# 3065HRPICZ register map
File version: 1.0
Registers are 32-bit, access per field, reset 0x0 unless marked. A register's access mark holds for its fields unless they carry their own. Offsets are from the block's base; [hi:lo] are bit positions.

## APT0 — APT_REG peripheral interface
Base 0x14A00000
Same registers: APT1 0x14A01000, APT2 0x14A02000, APT6 0x14A06000, APT7 0x14A07000, APT8 0x14A08000
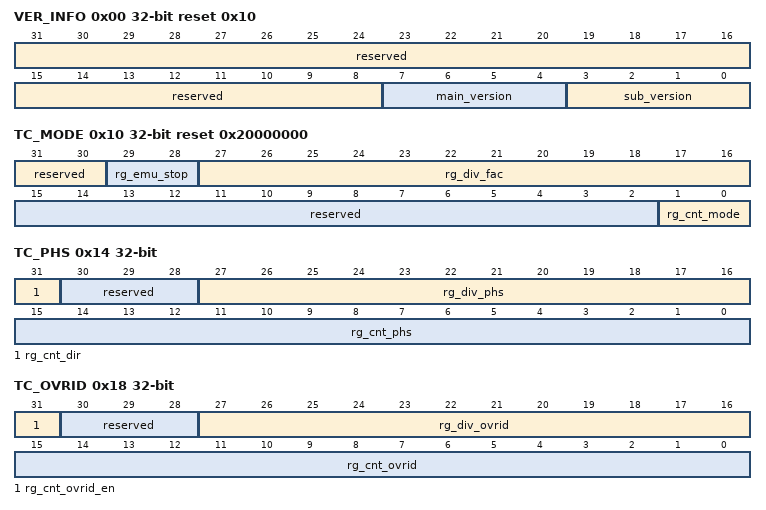
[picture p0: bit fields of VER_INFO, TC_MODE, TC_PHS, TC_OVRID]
0x00 VER_INFO ro reset 0x10 — 版本信息寄存器。
  [31:8] reserved — 保留。
  [7:4] main_version — 主版本号。
  [3:0] sub_version — 子版本号。
0x10 TC_MODE reset 0x20000000 — 计数模式寄存器。
  [31:30] reserved ro — 保留。
  [29:28] rg_emu_stop rw — CPU debug模式，APT停止的方式。注意，如果停止APT，那么在CPU debug模式下，整个APT都会停止工作，包括输出控制功能。 0x：不停止； 10：停止分频计数器（DIVCNT）和时基计数器（TCCNT）； 11：停止APT。
  [27:16] rg_div_fac rw — 分频系数。 分频倍数 =分频系数 +1。
  [15:2] reserved ro — 保留。
  [1:0] rg_cnt_mode rw — 时基计数器（TCCNT）的工作模式。 00：递增计数； 01：递减计数； 10：先增后减计数； 11：冻结。
0x14 TC_PHS — 计数相位控制寄存器。
  [31] rg_cnt_dir rw — 当 APTCNTSYNC 有效时，更新时基计数器（TCCNT）的计数方向，仅在先增后减 计数模式有效。 0：递减； 1：递增。
  [30:28] reserved ro — 保留。
  [27:16] rg_div_phs rw — 当 APTCNTSYNC 有效时，更新分频计数器（DIVCNT）的计数值。
  [15:0] rg_cnt_phs rw — 当 APTCNTSYNC 有效时，更新时基计数器（TCCNT）的计数值。
0x18 TC_OVRID — 计数器初始化寄存器。
  [31] rg_cnt_ovrid_en rw write-1-clears — 时基计数器（TCCNT）和分频计数器（DIVCNT）的初始化使能。 0：无效； 1：初始化时基计数器（TCCNT）和分频计数器（DIVCNT）的计数值。
  [30:28] reserved ro — 保留。
  [27:16] rg_div_ovrid rw — 初始化分频计数(DIVCNT）的计数值。
  [15:0] rg_cnt_ovrid rw — 初始化时基计数（TCCNT）的计数值。
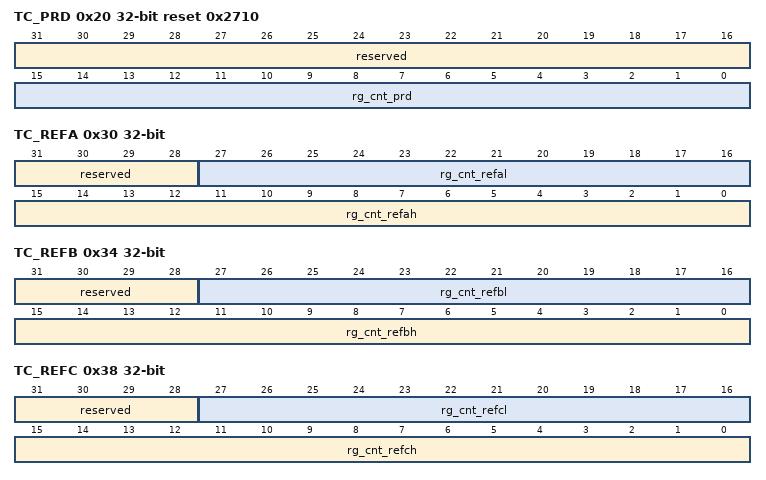
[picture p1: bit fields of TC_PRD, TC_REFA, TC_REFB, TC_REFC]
0x20 TC_PRD reset 0x2710 — 计数周期寄存器。
  [31:16] reserved ro — 保留。
  [15:0] rg_cnt_prd rw — 时基计数器（TCCNT）的计数周期。
0x30 TC_REFA — 计数参考值A寄存器。
  [31:28] reserved ro — 保留。
  [27:16] rg_cnt_refal rw — 分频计数器（DIVCNT）的参考值A，应当小于或等于分频系数。
  [15:0] rg_cnt_refah rw — 时基计数器（TCCNT）的参考值 A，应当小于或等于计数周期。
0x34 TC_REFB — 计数参考值B寄存器。
  [31:28] reserved ro — 保留。
  [27:16] rg_cnt_refbl rw — 分频计数器（DIVCNT）的参考值B，应当小于或等于分频系数。
  [15:0] rg_cnt_refbh rw — 时基计数器（TCCNT）的参考值B，应当小于或等于计数周期。
0x38 TC_REFC — 计数参考值C寄存器。
  [31:28] reserved ro — 保留。
  [27:16] rg_cnt_refcl rw — 分频计数器（DIVCNT）的参考值C，应当小于或等于分频系数。
  [15:0] rg_cnt_refch rw — 时基计数器（TCCNT）的参考值C，应当小于或等于计数周期。
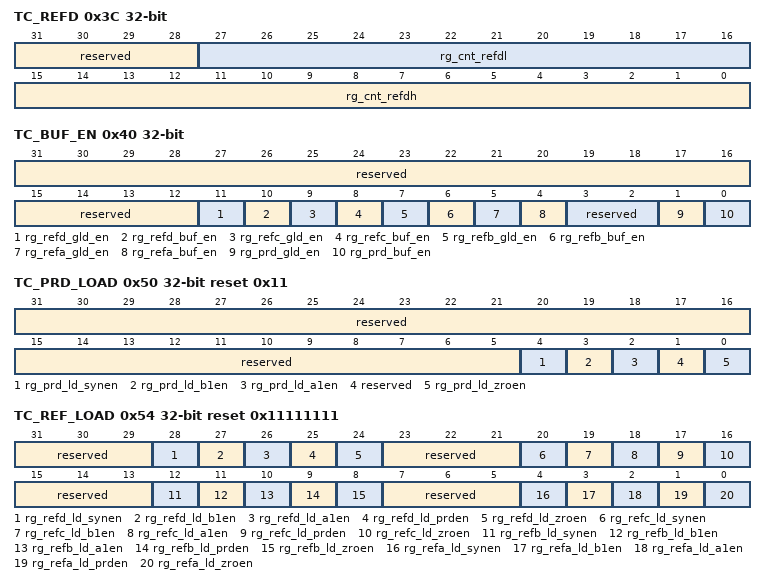
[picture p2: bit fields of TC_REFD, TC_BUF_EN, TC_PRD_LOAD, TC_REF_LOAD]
0x3C TC_REFD — 计数参考值D寄存器。
  [31:28] reserved ro — 保留。
  [27:16] rg_cnt_refdl rw — 分频计数器（DIVCNT）的参考值D，应当小于或等于分频系数。
  [15:0] rg_cnt_refdh rw — 时基计数器（TCCNT）的参考值D，应当小于或等于计数周期。
0x40 TC_BUF_EN — 计数器缓存使能寄存器。
  [31:12] reserved ro — 保留。
  [11] rg_refd_gld_en rw — TC_REFD 寄存器的全局加载使能。 0：不使能； 1：使能。
  [10] rg_refd_buf_en rw — TC_REFD 寄存器的缓存使能。 0：不使能； 1：使能。
  [9] rg_refc_gld_en rw — TC_REFC 寄存器的全局加载使能。 0：不使能； 1：使能。
  [8] rg_refc_buf_en rw — TC_REFC 寄存器的缓存使能。 0：不使能； 1：使能。
  [7] rg_refb_gld_en rw — TC_REFB 寄存器的全局加载使能。 0：不使能； 1：使能。
  [6] rg_refb_buf_en rw — TC_REFB 寄存器的缓存使能。 0：不使能； 1：使能。
  [5] rg_refa_gld_en rw — TC_REFA 寄存器的全局加载使能。 0：不使能； 1：使能。
  [4] rg_refa_buf_en rw — TC_REFA 寄存器的缓存使能。 0：不使能； 1：使能。
  [3:2] reserved ro — 保留。
  [1] rg_prd_gld_en rw — TC_PRD 寄存器的全局加载使能。 0：不使能； 1：使能。
  [0] rg_prd_buf_en rw — TC_PRD 寄存器的缓存使能。 0：不使能； 1：使能。
0x50 TC_PRD_LOAD reset 0x11 — 计数周期寄存器独立加载触发信号选择寄存器。
  [31:5] reserved ro — 保留。
  [4] rg_prd_ld_synen rw — 选择 APTxSYNCI 有效时，是否使能TC_PRD 寄存器的独立加载。 0：不使能； 1：使能。
  [3] rg_prd_ld_b1en rw — 选择 EMEVTB1 有效时，是否使能TC_PRD 寄存器的独立加载。 0：不使能； 1：使能。
  [2] rg_prd_ld_a1en rw — 选择 EMEVTA1 有效时，是否使能TC_PRD 寄存器的独立加载。 0：不使能； 1：使能。
  [1] reserved ro — 保留。
  [0] rg_prd_ld_zroen rw — 选择 CNT_ZERO 有效时，是否使能TC_PRD 寄存器的独立加载。 0：不使能； 1：使能。
0x54 TC_REF_LOAD reset 0x11111111 — 计数参考值寄存器独立加载触发信号选择寄存器。
  [31:29] reserved ro — 保留。
  [28] rg_refd_ld_synen rw — 选择 APTxSYNCI 有效时，是否使能TC_REFD 寄存器的独立加载。 0：不使能； 1：使能。
  [27] rg_refd_ld_b1en rw — 选择 EMEVTB1 有效时，是否使能TC_REFD 寄存器的独立加载。 0：不使能； 1：使能。
  [26] rg_refd_ld_a1en rw — 选择 EMEVTA1 有效时，是否使能TC_REFD 寄存器的独立加载。 0：不使能； 1：使能。
  [25] rg_refd_ld_prden rw — 选择 CNT_PRD 有效时，是否使能TC_REFD 寄存器的独立加载。 0：不使能； 1：使能。
  [24] rg_refd_ld_zroen rw — 选择 CNT_ZERO 有效时，是否使能TC_REFD 寄存器的独立加载。 0：不使能； 1：使能。
  [23:21] reserved ro — 保留。
  [20] rg_refc_ld_synen rw — 选择 APTxSYNCI 有效时，是否使能TC_REFC 寄存器的独立加载。 0：不使能； 1：使能。
  [19] rg_refc_ld_b1en rw — 当选择 EMEVTB1 有效时，是否使能TC_REFC 寄存器的独立加载。 0：不使能； 1：使能。
  [18] rg_refc_ld_a1en rw — 选择 EMEVTA1 有效时，是否使能TC_REFC 寄存器的独立加载。 0：不使能； 1：使能。
  [17] rg_refc_ld_prden rw — 选择 CNT_PRD 有效时，是否使能TC_REFC 寄存器的独立加载。 0：不使能； 1：使能。
  [16] rg_refc_ld_zroen rw — 选择 CNT_ZERO 有效时，是否使能TC_REFC 寄存器的独立加载。 0：不使能； 1：使能。
  [15:13] reserved ro — 保留。
  [12] rg_refb_ld_synen rw — 选择 APTxSYNCI 有效时，是否使能TC_REFB 寄存器的独立加载。 0：不使能； 1：使能。
  [11] rg_refb_ld_b1en rw — 选择 EMEVTB1 有效时，是否使能TC_REFB 寄存器的独立加载。 0：不使能； 1：使能。
  [10] rg_refb_ld_a1en rw — 选择 EMEVTA1 有效时，是否使能TC_REFB 寄存器的独立加载。 0：不使能； 1：使能。
  [9] rg_refb_ld_prden rw — 选择 CNT_PRD 有效时，是否使能TC_REFB 寄存器的独立加载。 0：不使能； 1：使能。
  [8] rg_refb_ld_zroen rw — 选择 CNT_ZERO 有效时，是否使能TC_REFB 寄存器的独立加载。 0：不使能； 1：使能。
  [7:5] reserved ro — 保留。
  [4] rg_refa_ld_synen rw — 选择 APTxSYNCI 有效时，是否使能TC_REFA 寄存器的独立加载。 0：不使能； 1：使能。
  [3] rg_refa_ld_b1en rw — 选择 EMEVTB1 有效时，是否使能TC_REFA 寄存器的独立加载。 0：不使能； 1：使能。
  [2] rg_refa_ld_a1en rw — 选择 EMEVTA1 有效时，是否使能TC_REFA 寄存器的独立加载。 0：不使能； 1：使能。
  [1] rg_refa_ld_prden rw — 选择 CNT_PRD 有效时，是否使能TC_REFA 寄存器的独立加载。 0：不使能； 1：使能。
  [0] rg_refa_ld_zroen rw — 选择 CNT_ZERO 有效时，是否使能TC_REFA 寄存器的独立加载。 0：不使能； 1：使能。
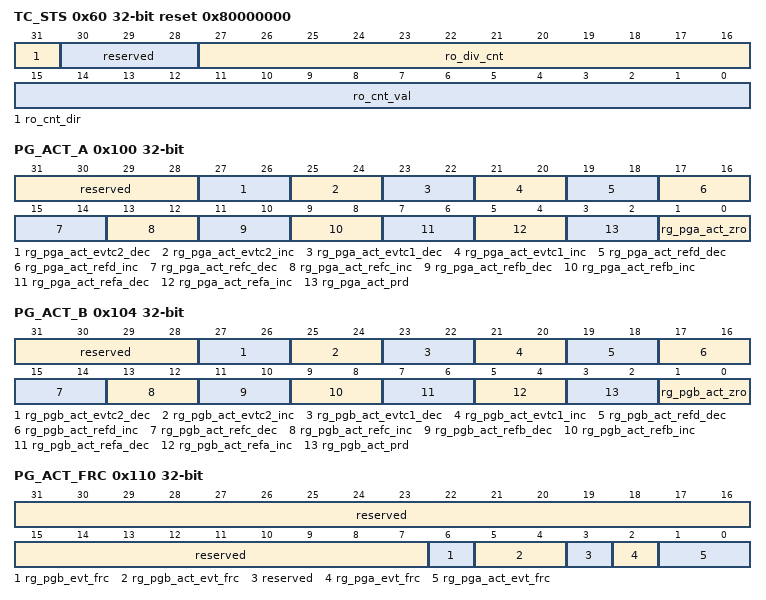
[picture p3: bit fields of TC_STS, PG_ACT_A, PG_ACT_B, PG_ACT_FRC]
0x60 TC_STS ro reset 0x80000000 — 计数状态寄存器。
  [31] ro_cnt_dir — 时基计数器（TCCNT）的当前计数方向。 0：递减计数； 1：递增计数。
  [30:28] reserved — 保留。
  [27:16] ro_div_cnt — 分频计数器（DIVCNT）的当前计数值。
  [15:0] ro_cnt_val — 时基计数器（TCCNT）的当前计数值。
0x100 PG_ACT_A — PG_PWMA 动作配置寄存器。
  [31:28] reserved ro — 保留。
  [27:26] rg_pga_act_evtc2_dec rw — AEVTC2 有效且 TCCNT 计数方向递减时， PG_PWMA 的动作。 00：无影响； 01：置为低电平； 10：置为高电平； 11：翻转电平。
  [25:24] rg_pga_act_evtc2_inc rw — AEVTC2 有效且 TCCNT 计数方向递增时， PG_PWMA 的动作。 00：无影响； 01：置为低电平； 10：置为高电平； 11：翻转电平。
  [23:22] rg_pga_act_evtc1_dec rw — AEVTC1 有效且 TCCNT 计数方向递减时， PG_PWMA 的动作。 00：无影响； 01：置为低电平； 10：置为高电平； 11：翻转电平。
  [21:20] rg_pga_act_evtc1_inc rw — AEVTC1 有效且 TCCNT 计数方向递增时， PG_PWMA 的动作。 00：无影响； 01：置为低电平； 10：置为高电平； 11：翻转电平。
  [19:18] rg_pga_act_refd_dec rw — CNT_REFD 有效且 TCCNT 计数方向递减时， PG_PWMA 的动作。 00：无影响； 01：置为低电平； 10：置为高电平； 11：翻转电平。
  [17:16] rg_pga_act_refd_inc rw — CNT_REFD 有效且 TCCNT 计数方向递增时， PG_PWMA 的动作。 00：无影响； 01：置为低电平； 10：置为高电平； 11：翻转电平。
  [15:14] rg_pga_act_refc_dec rw — CNT_REFC 有效且 TCCNT 计数方向递减时， PG_PWMA 的动作。 00：无影响； 01：置为低电平； 10：置为高电平； 11：翻转电平。
  [13:12] rg_pga_act_refc_inc rw — CNT_REFC 有效且 TCCNT 计数方向递增时， PG_PWMA 的动作。 00：无影响； 01：置为低电平； 10：置为高电平； 11：翻转电平。
  [11:10] rg_pga_act_refb_dec rw — CNT_REFB 有效且 TCCNT 计数方向递减时， PG_PWMA 的动作。 00：无影响； 01：置为低电平； 10：置为高电平； 11：翻转电平。
  [9:8] rg_pga_act_refb_inc rw — CNT_REFB 有效且 TCCNT 计数方向递增时， PG_PWMA 的动作。 00：无影响； 01：置为低电平； 10：置为高电平； 11：翻转电平。
  [7:6] rg_pga_act_refa_dec rw — CNT_REFA 有效且 TCCNT 计数方向递减时， PG_PWMA 的动作。 00：无影响； 01：置为低电平； 10：置为高电平； 11：翻转电平。
  [5:4] rg_pga_act_refa_inc rw — CNT_REFA 有效且 TCCNT 计数方向递增时， PG_PWMA 的动作。 00：无影响； 01：置为低电平； 10：置为高电平； 11：翻转电平。
  [3:2] rg_pga_act_prd rw — CNT_PRD 有效时，PG_PWMA 的动作。 00：无影响； 01：置为低电平； 10：置为高电平； 11：翻转电平。
  [1:0] rg_pga_act_zro rw — CNT_ZERO 有效时,PG_PWMA 的动作。 00：无影响； 01：置为低电平； 10：置为高电平； 11：翻转电平。
0x104 PG_ACT_B — PG_PWMB 动作配置寄存器。
  [31:28] reserved ro — 保留。
  [27:26] rg_pgb_act_evtc2_dec rw — BEVTC2有效且TCCNT计数方向递减时，PG_PWMB的动作。 00：无影响； 01：置为低电平； 10：置为高电平； 11：翻转电平。
  [25:24] rg_pgb_act_evtc2_inc rw — BEVTC2有效且TCCNT计数方向递增时，PG_PWMB的动作。 00：无影响； 01：置为低电平； 10：置为高电平； 11：翻转电平。
  [23:22] rg_pgb_act_evtc1_dec rw — BEVTC1有效且TCCNT计数方向递减时，PG_PWMB的动作。 00：无影响； 01：置为低电平； 10：置为高电平； 11：翻转电平。
  [21:20] rg_pgb_act_evtc1_inc rw — BEVTC1有效且TCCNT计数方向递增时，PG_PWMB的动作。 00：无影响； 01：置为低电平； 10：置为高电平； 11：翻转电平。
  [19:18] rg_pgb_act_refd_dec rw — CNT_REFD 有效且 TCCNT 计数方向递减时， PG_PWMB 的动作。 00：无影响； 01：置为低电平； 10：置为高电平； 11：翻转电平。
  [17:16] rg_pgb_act_refd_inc rw — CNT_REFD 有效且 TCCNT 计数方向递增时， PG_PWMB 的动作。 00：无影响； 01：置为低电平； 10：置为高电平； 11：翻转电平。
  [15:14] rg_pgb_act_refc_dec rw — CNT_REFC 有效且 TCCNT 计数方向递减时， PG_PWMB 的动作。 00：无影响； 01：置为低电平； 10：置为高电平； 11：翻转电平。
  [13:12] rg_pgb_act_refc_inc rw — CNT_REFC 有效且 TCCNT 计数方向递增时， PG_PWMB 的动作。 00：无影响； 01：置为低电平； 10：置为高电平； 11：翻转电平。
  [11:10] rg_pgb_act_refb_dec rw — CNT_REFB 有效且 TCCNT 计数方向递减时， PG_PWMB 的动作。 00：无影响； 01：置为低电平； 10：置为高电平； 11：翻转电平。
  [9:8] rg_pgb_act_refb_inc rw — CNT_REFB 有效且 TCCNT 计数方向递增时， PG_PWMB 的动作。 00：无影响； 01：置为低电平； 10：置为高电平； 11：翻转电平。
  [7:6] rg_pgb_act_refa_dec rw — CNT_REFA 有效且 TCCNT 计数方向递减时， PG_PWMB 的动作。 00：无影响； 01：置为低电平； 10：置为高电平； 11：翻转电平。
  [5:4] rg_pgb_act_refa_inc rw — CNT_REFA 有效且 TCCNT 计数方向递增时， PG_PWMB 的动作。 00：无影响； 01：置为低电平； 10：置为高电平； 11：翻转电平。
  [3:2] rg_pgb_act_prd rw — CNT_PRD 有效时，PG_PWMB 的动作。 00：无影响； 01：置为低电平； 10：置为高电平； 11：翻转电平。
  [1:0] rg_pgb_act_zro rw — CNT_ZERO 有效时,PG_PWMB 的动作。 00：无影响； 01：置为低电平； 10：置为高电平； 11：翻转电平。
0x110 PG_ACT_FRC — 强制动作配置寄存器。
  [31:7] reserved ro — 保留。
  [6] rg_pgb_evt_frc rw write-1-clears — 软件强制 PG_PWMB 动作，每次写 1 产生一次PG_PWMB 动作，然后自动清零。 0：写 0 无效； 1：写 1 有效。
  [5:4] rg_pgb_act_evt_frc rw — 软件强制 PG_PWMB 动作有效时，PG_PWMB 的动作。 00：无影响； 01：置为低电平； 10：置为高电平； 11：翻转电平。
  [3] reserved ro — 保留。
  [2] rg_pga_evt_frc rw write-1-clears — 软件强制 PG_PWMA 动作，每次写 1 产生一次PG_PWMA 动作，然后自动清零。 0：写 0 无效； 1：写 1 有效。
  [1:0] rg_pga_act_evt_frc rw — 软件强制 PG_PWMA 动作有效时，PG_PWMA 的动作。 00：无影响； 01：置为低电平； 10：置为高电平； 11：翻转电平。
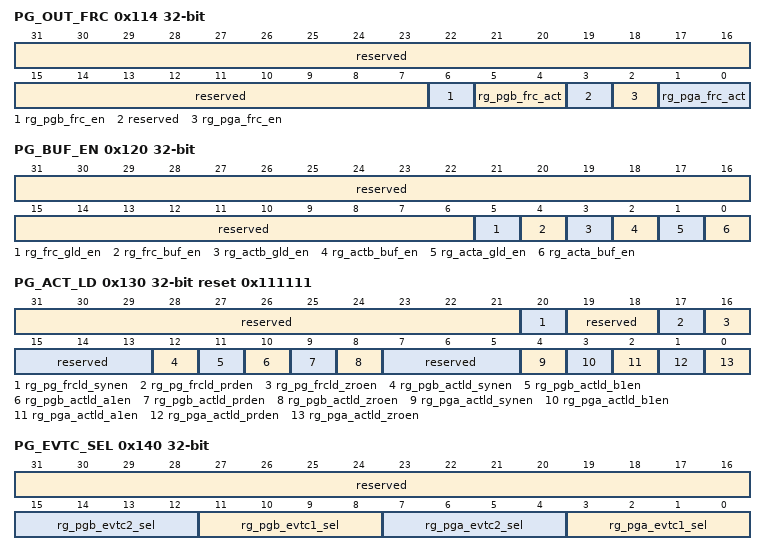
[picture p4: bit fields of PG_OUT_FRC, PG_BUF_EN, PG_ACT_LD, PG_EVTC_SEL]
0x114 PG_OUT_FRC — 强制输出配置寄存器。
  [31:7] reserved ro — 保留。
  [6] rg_pgb_frc_en rw — PG_PWMB 软件强制输出使能。 0：不使能； 1：使能。
  [5:4] rg_pgb_frc_act rw — PG_PWMB 软件强制输出使能时，PG_PWMB 的输出状态。 00：锁定电平； 01：置为低电平； 10：置为高电平； 11：保留。
  [3] reserved ro — 保留。
  [2] rg_pga_frc_en rw — PG_PWMA 软件强制输出使能。 0：不使能； 1：使能。
  [1:0] rg_pga_frc_act rw — PG_PWMA 软件强制输出使能时，PG_PWMA 的输出状态。 00：锁定电平； 01：置为低电平； 10：置为高电平； 11：保留。
0x120 PG_BUF_EN — 波形生成缓存使能寄存器。
  [31:6] reserved ro — 保留。
  [5] rg_frc_gld_en rw — PG_ACT_FRC 寄存器的全局加载使能。 0：不使能； 1：使能。
  [4] rg_frc_buf_en rw — PG_ACT_FRC 寄存器的缓存使能。 0：不使能； 1：使能。
  [3] rg_actb_gld_en rw — PG_ACT_B 寄存器的全局加载使能。 0：不使能； 1：使能。
  [2] rg_actb_buf_en rw — PG_ACT_B 寄存器的缓存使能。 0：不使能； 1：使能。
  [1] rg_acta_gld_en rw — PG_ACT_A 寄存器的全局加载使能。 0：不使能； 1：使能。
  [0] rg_acta_buf_en rw — PG_ACT_A 寄存器的缓存使能。 0：不使能； 1：使能。
0x130 PG_ACT_LD reset 0x111111 — 波形生成动作独立加载触发信号选择寄存器。
  [31:21] reserved ro — 保留。
  [20] rg_pg_frcld_synen rw — 选择 APTxSYNCI 有效时，是否使能PG_ACT_FRC 寄存器的独立加载。 0：不使能； 1：使能。
  [19:18] reserved ro — 保留。
  [17] rg_pg_frcld_prden rw — 选择 CNT_PRD 有效时，是否使能PG_ACT_FRC 寄存器的独立加载。 0：不使能； 1：使能。
  [16] rg_pg_frcld_zroen rw — 选择 CNT_ZERO 有效时，是否使能PG_ACT_FRC 寄存器的独立加载。 0：不使能； 1：使能。
  [15:13] reserved ro — 保留。
  [12] rg_pgb_actld_synen rw — 选择 APTxSYNCI 有效时，是否使能PG_ACT_B 寄存器的独立加载。 0：不使能； 1：使能。
  [11] rg_pgb_actld_b1en rw — 选择 EMEVTB1 有效时，是否使能PG_ACT_B 寄存器的独立加载。 0：不使能； 1：使能。
  [10] rg_pgb_actld_a1en rw — 选择 EMEVTA1 有效时，是否使能PG_ACT_B 寄存器的独立加载。 0：不使能； 1：使能。
  [9] rg_pgb_actld_prden rw — 选择 CNT_PRD 有效时，是否使能PG_ACT_B 寄存器的独立加载。 0：不使能； 1：使能。
  [8] rg_pgb_actld_zroen rw — 选择 CNT_ZERO 有效时，是否使能PG_ACT_B 寄存器的独立加载。 0：不使能； 1：使能。
  [7:5] reserved ro — 保留。
  [4] rg_pga_actld_synen rw — 选择 APTxSYNCI 有效时，是否使能PG_ACT_A 寄存器的独立加载。 0：不使能； 1：使能。
  [3] rg_pga_actld_b1en rw — 选择 EMEVTB1 有效时，是否使能PG_ACT_A 寄存器的独立加载。 0：不使能； 1：使能。
  [2] rg_pga_actld_a1en rw — 选择 EMEVTA1 有效时，是否使能PG_ACT_A 寄存器的独立加载。 0：不使能； 1：使能。
  [1] rg_pga_actld_prden rw — 选择 CNT_PRD 有效时，是否使能PG_ACT_A 寄存器的独立加载。 0：不使能； 1：使能。
  [0] rg_pga_actld_zroen rw — 选择 CNT_ZERO 有效时，是否使能PG_ACT_A 寄存器的独立加载。 0：不使能； 1：使能。
0x140 PG_EVTC_SEL — 波形生成事件 C 触发源选择寄存器。
  [31:16] reserved ro — 保留。
  [15:12] rg_pgb_evtc2_sel rw — BEVTC2 触发源选择。 0x1： EMEVTA1_TEMP； 0x2： EMEVTA2_TEMP； 0x3： EMEVTB1_TEMP； 0x4： EMEVTB2_TEMP； 0x5： EMEVTFILT； 0x6： TRIP1； 0x7： TRIP2； 0x8： TRIP3； 0x9： APTxSYNCI； 其它：禁止产生 BEVTC2。
  [11:8] rg_pgb_evtc1_sel rw — BEVTC1 触发源选择。 0x1： EMEVTA1_TEMP； 0x2： EMEVTA2_TEMP； 0x3： EMEVTB1_TEMP； 0x4： EMEVTB2_TEMP； 0x5： EMEVTFILT； 0x6： TRIP1； 0x7： TRIP2； 0x8： TRIP3； 0x9： APTxSYNCI； 其它：禁止产生 BEVTC1。
  [7:4] rg_pga_evtc2_sel rw — AEVTC2 触发源选择。 0x1： EMEVTA1_TEMP；0x2： EMEVTA2_TEMP； 0x3： EMEVTB1_TEMP； 0x4： EMEVTB2_TEMP； 0x5： EMEVTFILT； 0x6： TRIP1； 0x7： TRIP2； 0x8： TRIP3； 0x9： APTxSYNCI； 其它：禁止产生 AEVTC2。
  [3:0] rg_pga_evtc1_sel rw — AEVTC1 触发源选择。 0x1： EMEVTA1_TEMP； 0x2： EMEVTA2_TEMP； 0x3： EMEVTB1_TEMP； 0x4： EMEVTB2_TEMP； 0x5： EMEVTFILT； 0x6： TRIP1； 0x7： TRIP2； 0x8： TRIP3； 0x9： APTxSYNCI； 其它：禁止产生 AEVTC1。
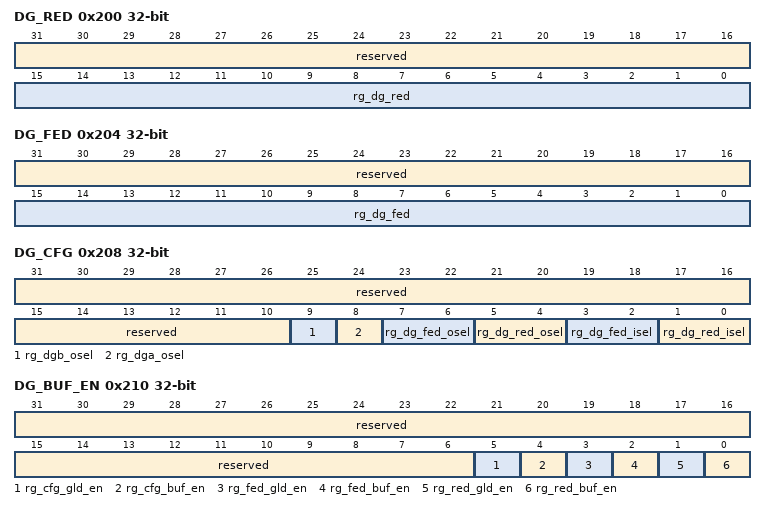
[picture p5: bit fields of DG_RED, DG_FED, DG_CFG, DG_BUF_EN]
0x200 DG_RED — 死区上升沿延时配置寄存器。
  [31:16] reserved ro — 保留。
  [15:0] rg_dg_red rw — 死区上升沿延时配置。
0x204 DG_FED — 死区下降沿延时配置寄存器。
  [31:16] reserved ro — 保留。
  [15:0] rg_dg_fed rw — 死区下降沿延时配置。
0x208 DG_CFG — 死区配置寄存器。
  [31:10] reserved ro — 保留。
  [9] rg_dgb_osel rw — 选择 DG_PWMB 的源。 0：选择 PWM_FED_POL 作为DG_PWMB； 1：选择 PWM_RED_POL 作为DG_PWMB。
  [8] rg_dga_osel rw — 选择 DG_PWMA 的源。 0：选择 PWM_RED_POL 作为DG_PWMA； 1：选择 PWM_FED_POL 作为DG_PWMA。
  [7:6] rg_dg_fed_osel rw — 选择PWM_FED_POL的源。 0x：选择PWM_FED_AFTER作为PWM_FED_POL； 10：选择PWM_FED_AFTER取反后作为PWM_FED_POL； 11：选择PG_PWMB作为PWM_FED_POL。
  [5:4] rg_dg_red_osel rw — 选择PWM_RED_POL的源。 0x：选择PWM_RED_AFTER作为PWM_RED_POL； 10：选择PWM_RED_AFTER取反后作为PWM_RED_POL； 11：选择PG_PWMA作为PWM_RED_POL。
  [3:2] rg_dg_fed_isel rw — 选择PWM_FED_BEFORE的源。 00：选择PG_PWMB作为PWM_FED_BEFORE； 01：选择PG_PWMA作为PWM_FED_BEFORE； 10：选择PWM_RED_BEFORE作为PWM_FED_BEFORE； 11：将PWM_FED_BEFORE固定为低电平。
  [1:0] rg_dg_red_isel rw — 选择PWM_RED_BEFORE的源。 x0：选择PG_PWMA作为PWM_RED_BEFORE； x1：选择PG_PWMB作为PWM_RED_BEFORE。
0x210 DG_BUF_EN — 死区生成缓存使能寄存器。
  [31:6] reserved ro — 保留。
  [5] rg_cfg_gld_en rw — DG_CFG寄存器的全局加载使能。 0：不使能； 1：使能。
  [4] rg_cfg_buf_en rw — DG_CFG寄存器的缓存使能。 0：不使能； 1：使能。
  [3] rg_fed_gld_en rw — DG_CFG寄存器的全局加载使能。 0：不使能； 1：使能。
  [2] rg_fed_buf_en rw — DG_FED寄存器的缓存使能。 0：不使能； 1：使能。
  [1] rg_red_gld_en rw — DG_RED寄存器的全局加载使能。 0：不使能； 1：使能。
  [0] rg_red_buf_en rw — DG_RED寄存器的缓存使能。 0：不使能； 1：使能。
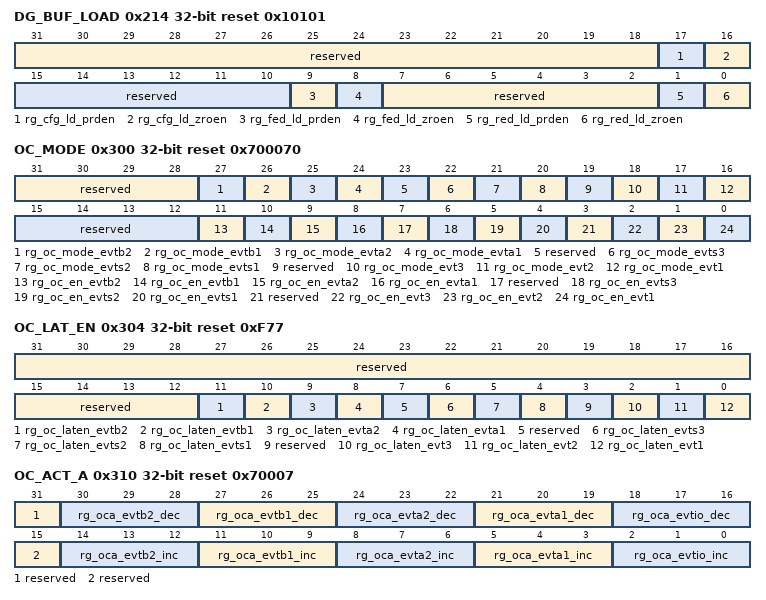
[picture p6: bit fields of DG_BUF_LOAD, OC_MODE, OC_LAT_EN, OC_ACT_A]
0x214 DG_BUF_LOAD reset 0x10101 — 死区生成独立加载触发信号选择寄存器。
  [31:18] reserved ro — 保留。
  [17] rg_cfg_ld_prden rw — 选择CNT_PRD有效时，是否使能DG_CFG寄存器的独立加载。 0：不使能； 1：使能。
  [16] rg_cfg_ld_zroen rw — 选择CNT_ZERO有效时，是否使能DG_CFG寄存器的独立加载。 0：不使能； 1：使能。
  [15:10] reserved ro — 保留。
  [9] rg_fed_ld_prden rw — 选择CNT_PRD有效时，是否使能DG_FED寄存器的独立加载。 0：不使能； 1：使能。
  [8] rg_fed_ld_zroen rw — 选择CNT_ZERO有效时，是否使能DG_FED寄存器的独立加载。 0：不使能； 1：使能。
  [7:2] reserved ro — 保留。
  [1] rg_red_ld_prden rw — 选择CNT_PRD有效时，是否使能DG_RED寄存器的独立加载。 0：不使能； 1：使能。
  [0] rg_red_ld_zroen rw — 选择CNT_ZERO有效时，是否使能DG_RED寄存器的独立加载。 0：不使能； 1：使能。
0x300 OC_MODE reset 0x700070 — 输出保护模式寄存器。
  [31:28] reserved ro — 保留。
  [27] rg_oc_mode_evtb2 rw — EMEVTB2 的输出保护模式选择。 0：持续性保护； 1：周期性保护。
  [26] rg_oc_mode_evtb1 rw — EMEVTB1 的输出保护模式选择。 0：持续性保护； 1：周期性保护。
  [25] rg_oc_mode_evta2 rw — EMEVTA2 的输出保护模式选择。 0：持续性保护； 1：周期性保护。
  [24] rg_oc_mode_evta1 rw — EMEVTA1 的输出保护模式选择。 0：持续性保护； 1：周期性保护。
  [23] reserved ro — 保留。
  [22] rg_oc_mode_evts3 rw — TRIP11 的输出保护模式选择。 0：持续性保护； 1：周期性保护。
  [21] rg_oc_mode_evts2 rw — TRIP10 的输出保护模式选择。 0：持续性保护； 1：周期性保护。
  [20] rg_oc_mode_evts1 rw — TRIP9 的输出保护模式选择。 0：持续性保护； 1：周期性保护。
  [19] reserved ro — 保留。
  [18] rg_oc_mode_evt3 rw — TRIP3 的输出保护模式选择。 0：持续性保护； 1：周期性保护。
  [17] rg_oc_mode_evt2 rw — TRIP2 的输出保护模式选择。 0：持续性保护； 1：周期性保护。
  [16] rg_oc_mode_evt1 rw — TRIP1 的输出保护模式选择。 0：持续性保护； 1：周期性保护。
  [15:12] reserved ro — 保留。
  [11] rg_oc_en_evtb2 rw — EMEVTB2 的输出保护使能。 0：不使能； 1：使能。
  [10] rg_oc_en_evtb1 rw — EMEVTB1 的输出保护使能。 0：不使能； 1：使能。
  [9] rg_oc_en_evta2 rw — EMEVTA2 的输出保护使能。 0：不使能； 1：使能。
  [8] rg_oc_en_evta1 rw — EMEVTA1 的输出保护使能。 0：不使能； 1：使能。
  [7] reserved ro — 保留。
  [6] rg_oc_en_evts3 rw — TRIP11的输出保护使能。 0：不使能； 1：使能。
  [5] rg_oc_en_evts2 rw — TRIP10 的输出保护使能。 0：不使能； 1：使能。
  [4] rg_oc_en_evts1 rw — TRIP9 的输出保护使能。 0：不使能； 1：使能。
  [3] reserved ro — 保留。
  [2] rg_oc_en_evt3 rw — TRIP3 的输出保护使能。 0：不使能； 1：使能。
  [1] rg_oc_en_evt2 rw — TRIP2 的输出保护使能。 0：不使能； 1：使能。
  [0] rg_oc_en_evt1 rw — TRIP1 的输出保护使能。 0：不使能； 1：使能。
0x304 OC_LAT_EN reset 0xF77 — 故障信号锁存使能寄存器。
  [31:12] reserved ro — 保留。
  [11] rg_oc_laten_evtb2 rw — EMEVTB2的锁存使能。 0：不使能； 1：使能。
  [10] rg_oc_laten_evtb1 rw — EMEVTB1的锁存使能。 0：不使能； 1：使能。
  [9] rg_oc_laten_evta2 rw — EMEVTA2的锁存使能。 0：不使能； 1：使能。
  [8] rg_oc_laten_evta1 rw — EMEVTA1的锁存使能。 0：不使能； 1：使能。
  [7] reserved ro — 保留。
  [6] rg_oc_laten_evts3 rw — TRIP11的锁存使能。 0：不使能； 1：使能。
  [5] rg_oc_laten_evts2 rw — TRIP10的锁存使能。 0：不使能； 1：使能。
  [4] rg_oc_laten_evts1 rw — TRIP9的锁存使能。 0：不使能； 1：使能。
  [3] reserved ro — 保留。
  [2] rg_oc_laten_evt3 rw — TRIP3的锁存使能。 0：不使能； 1：使能。
  [1] rg_oc_laten_evt2 rw — TRIP2的锁存使能。 0：不使能； 1：使能。
  [0] rg_oc_laten_evt1 rw — TRIP1的锁存使能。 0：不使能； 1：使能。
0x310 OC_ACT_A reset 0x70007 — APTx_PWMA 输出保护寄存器。
  [31] reserved ro — 保留。
  [30:28] rg_oca_evtb2_dec rw — EMEVTB2有效且TCCNT计数方向递减时，APTx_PWMA的输出状态。 000：不做任何动作； 001：低电平； 010：高电平； 011：锁定电平； 100：翻转电平； 其它：高阻态。
  [27:25] rg_oca_evtb1_dec rw — EMEVTB1有效且TCCNT计数方向递减时，APTx_PWMA的输出状态。 000：不做任何动作； 001：低电平； 010：高电平； 011：锁定电平； 100：翻转电平； 其它：高阻态。
  [24:22] rg_oca_evta2_dec rw — EMEVTA2有效且TCCNT计数方向递减时，APTx_PWMA的输出状态。 000：不做任何动作； 001：低电平； 010：高电平； 011：锁定电平； 100：翻转电平； 其它：高阻态。
  [21:19] rg_oca_evta1_dec rw — EMEVTA1有效且TCCNT计数方向递减时，APTx_PWMA的输出状态。 000：不做任何动作； 001：低电平； 010：高电平； 011：锁定电平； 100：翻转电平； 其它：高阻态。
  [18:16] rg_oca_evtio_dec rw — TRIP1-TRIP3或TRIP9-TRIP11有效且TCCNT计数方向递减时，APTx_PWMA的输出状态。 000：不做任何动作； 001：低电平； 010：高电平； 011：锁定电平； 100：翻转电平； 其它：高阻态。
  [15] reserved ro — 保留。
  [14:12] rg_oca_evtb2_inc rw — EMEVTB2有效且TCCNT计数方向递增时，APTx_PWMA的输出状态。 000：不做任何动作； 001：低电平； 010：高电平； 011：锁定电平； 100：翻转电平； 其它：高阻态。
  [11:9] rg_oca_evtb1_inc rw — EMEVTB1有效且TCCNT计数方向递增时，APTx_PWMA的输出状态。 000：不做任何动作； 001：低电平； 010：高电平； 011：锁定电平； 100：翻转电平； 其它：高阻态。
  [8:6] rg_oca_evta2_inc rw — EMEVTA2有效且TCCNT计数方向递增时，APTx_PWMA的输出状态。 000：不做任何动作； 001：低电平； 010：高电平； 011：锁定电平； 100：翻转电平； 其它：高阻态。
  [5:3] rg_oca_evta1_inc rw — EMEVTA1有效且TCCNT计数方向递增时，APTx_PWMA的输出状态。 000：不做任何动作； 001：低电平； 010：高电平； 011：锁定电平； 100：翻转电平； 其它：高阻态。
  [2:0] rg_oca_evtio_inc rw — TRIP1-TRIP3 或 TRIP9-TRIP11 有效且 TCCNT 计数方向递增时， APTx_PWMA 的输出状态。 000：不做任何动作； 001：低电平； 010：高电平； 011：锁定电平； 100：翻转电平； 其它：高阻态。
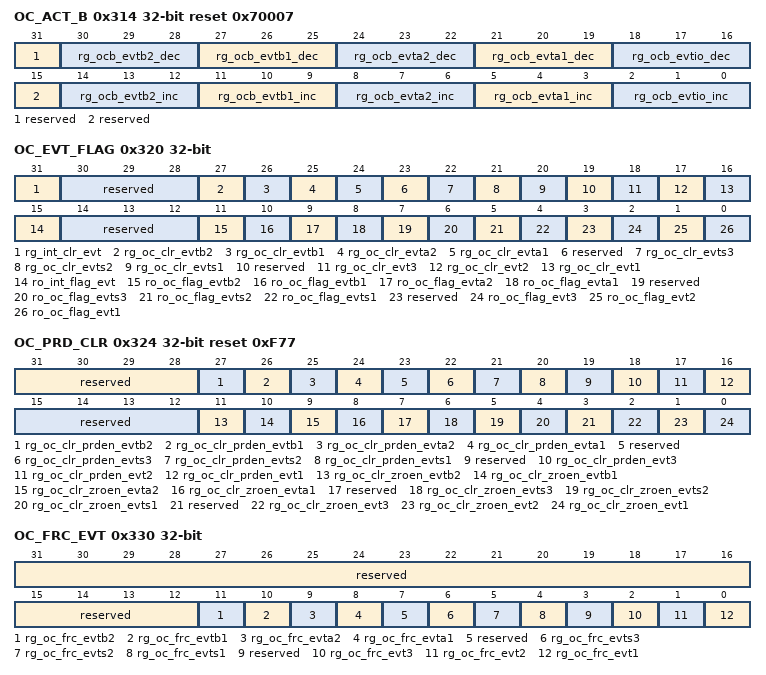
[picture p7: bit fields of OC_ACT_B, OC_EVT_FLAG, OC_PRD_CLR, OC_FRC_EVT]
0x314 OC_ACT_B reset 0x70007 — APTx_PWMB 输出保护寄存器。
  [31] reserved ro — 保留。
  [30:28] rg_ocb_evtb2_dec rw — EMEVTB2有效且TCCNT计数方向递减时，APTx_PWMB的输出状态。 000：不做任何动作； 001：低电平； 010：高电平； 011：锁定电平； 100：翻转电平； 其它：高阻态。
  [27:25] rg_ocb_evtb1_dec rw — EMEVTB1有效且TCCNT计数方向递减时，APTx_PWMB的输出状态。 000：不做任何动作； 001：低电平； 010：高电平； 011：锁定电平； 100：翻转电平； 其它：高阻态。
  [24:22] rg_ocb_evta2_dec rw — EMEVTA2有效且TCCNT计数方向递减时，APTx_PWMB的输出状态。 000：不做任何动作； 001：低电平； 010：高电平； 011：锁定电平； 100：翻转电平； 其它：高阻态。
  [21:19] rg_ocb_evta1_dec rw — EMEVTA1有效且TCCNT计数方向递减时，APTx_PWMB的输出状态。 000：不做任何动作； 001：低电平； 010：高电平； 011：锁定电平； 100：翻转电平； 其它：高阻态。
  [18:16] rg_ocb_evtio_dec rw — TRIP1-TRIP3或TRIP9-TRIP11有效且TCCNT计数方向递减时，APTx_PWMB的输出状态。 000：不做任何动作； 001：低电平； 010：高电平； 011：锁定电平； 100：翻转电平； 其它：高阻态。
  [15] reserved ro — 保留。
  [14:12] rg_ocb_evtb2_inc rw — EMEVTB2有效且TCCNT计数方向递增时，APTx_PWMB的输出状态。 000：不做任何动作； 001：低电平； 010：高电平； 011：锁定电平； 100：翻转电平； 其它：高阻态。
  [11:9] rg_ocb_evtb1_inc rw — EMEVTB1有效且TCCNT计数方向递增时，APTx_PWMB的输出状态。 000：不做任何动作； 001：低电平； 010：高电平； 011：锁定电平； 100：翻转电平； 其它：高阻态。
  [8:6] rg_ocb_evta2_inc rw — EMEVTA2有效且TCCNT计数方向递增时，APTx_PWMB的输出状态。 000：不做任何动作； 001：低电平； 010：高电平； 011：锁定电平； 100：翻转电平； 其它：高阻态。
  [5:3] rg_ocb_evta1_inc rw — EMEVTA1有效且TCCNT计数方向递增时，APTx_PWMB的输出状态。 000：不做任何动作； 001：低电平； 010：高电平； 011：锁定电平； 100：翻转电平； 其它：高阻态。
  [2:0] rg_ocb_evtio_inc rw — TRIP1-TRIP3或TRIP9-TRIP11有效且TCCNT计数方向递增时，APTx_PWMB的输出状态。 000：不做任何动作； 001：低电平； 010：高电平； 011：锁定电平； 100：翻转电平； 其它：高阻态。
0x320 OC_EVT_FLAG — 故障信号和事件中断标志寄存器。
  [31] rg_int_clr_evt rw write-1-clears — 事件中断APTxEVTINT的中断清除位，写1清0。 0：写0无效； 1：写1有效。
  [30:28] reserved ro — 保留。
  [27] rg_oc_clr_evtb2 rw write-1-clears — EMEVTB2故障信号标志的清除位，写1清0。 0：写0无效； 1：写1有效。
  [26] rg_oc_clr_evtb1 rw write-1-clears — EMEVTB1故障信号标志的清除位，写1清0。 0：写0无效； 1：写1有效。
  [25] rg_oc_clr_evta2 rw write-1-clears — EMEVTA2故障信号标志的清除位，写1清0。 0：写0无效； 1：写1有效。
  [24] rg_oc_clr_evta1 rw write-1-clears — EMEVTA1故障信号标志的清除位，写1清0。 0：写0无效； 1：写1有效。
  [23] reserved ro — 保留。
  [22] rg_oc_clr_evts3 rw write-1-clears — TRIP11故障信号标志的清除位，写1清0。 0：写0无效； 1：写1有效。
  [21] rg_oc_clr_evts2 rw write-1-clears — TRIP10故障信号标志的清除位，写1清0。 0：写0无效； 1：写1有效。
  [20] rg_oc_clr_evts1 rw write-1-clears — TRIP9故障信号标志的清除位，写1清0。 0：写0无效； 1：写1有效。
  [19] reserved ro — 保留。
  [18] rg_oc_clr_evt3 rw write-1-clears — TRIP3故障信号标志的清除位，写1清0。 0：写0无效； 1：写1有效。
  [17] rg_oc_clr_evt2 rw write-1-clears — TRIP2故障信号标志的清除位，写1清0。 0：写0无效； 1：写1有效。
  [16] rg_oc_clr_evt1 rw write-1-clears — TRIP1故障信号标志的清除位，写1清0。 0：写0无效； 1：写1有效。
  [15] ro_int_flag_evt ro — 事件中断APTxEVTINT的中断标志位。 0：APTxEVTINT无效； 1：APTxEVTINT有效。
  [14:12] reserved ro — 保留。
  [11] ro_oc_flag_evtb2 ro — EMEVTB2故障信号标志位。 0：EMEVTB2故障信号无效； 1：EMEVTB2故障信号有效。
  [10] ro_oc_flag_evtb1 ro — EMEVTB1故障信号标志位。 0：EMEVTB1故障信号无效； 1：EMEVTB1故障信号有效。
  [9] ro_oc_flag_evta2 ro — EMEVTA2故障信号标志位。 0：EMEVTA2故障信号无效； 1：EMEVTA2故障信号有效。
  [8] ro_oc_flag_evta1 ro — EMEVTA1故障信号标志位。 0：EMEVTA1故障信号无效； 1：EMEVTA1故障信号有效。
  [7] reserved ro — 保留。
  [6] ro_oc_flag_evts3 ro — TRIP11故障信号标志位。 0：TRIP11故障信号无效； 1：TRIP11故障信号有效。
  [5] ro_oc_flag_evts2 ro — TRIP10故障信号标志位。 0：TRIP10故障信号无效； 1：TRIP10故障信号有效。
  [4] ro_oc_flag_evts1 ro — TRIP9故障信号标志位。 0：TRIP9故障信号无效； 1：TRIP9故障信号有效。
  [3] reserved ro — 保留。
  [2] ro_oc_flag_evt3 ro — TRIP3故障信号标志位。 0：TRIP3故障信号无效； 1：TRIP3故障信号有效。
  [1] ro_oc_flag_evt2 ro — TRIP2故障信号标志位。 0：TRIP2故障信号无效； 1：TRIP2故障信号有效。
  [0] ro_oc_flag_evt1 ro — TRIP1故障信号标志位。 0：TRIP1故障信号无效； 1：TRIP1故障信号有效。
0x324 OC_PRD_CLR reset 0xF77 — 周期性保护自动清除寄存器。
  [31:28] reserved ro — 保留。
  [27] rg_oc_clr_prden_evtb2 rw — 当EMEVTB2设置成周期性保护时，选择是否在CNT_PRD有效时清除对APTx_PWMA/APTx_PWMB的保护。 0：不使能； 1：使能。
  [26] rg_oc_clr_prden_evtb1 rw — 当EMEVTB1设置成周期性保护时，选择是否在CNT_PRD有效时清除对APTx_PWMA/APTx_PWMB的保护。 0：不使能； 1：使能。
  [25] rg_oc_clr_prden_evta2 rw — 当EMEVTA2设置成周期性保护时，选择是否在CNT_PRD有效时清除对APTx_PWMA/APTx_PWMB的保护。 0：不使能； 1：使能。
  [24] rg_oc_clr_prden_evta1 rw — 当EMEVTA1设置成周期性保护时，选择是否在CNT_PRD有效时清除对APTx_PWMA/APTx_PWMB的保护。 0：不使能； 1：使能。
  [23] reserved ro — 保留。
  [22] rg_oc_clr_prden_evts3 rw — 当TRIP11设置成周期性保护时，选择是否在CNT_PRD有效时清除对APTx_PWMA/APTx_PWMB的保护。 0：不使能； 1：使能。
  [21] rg_oc_clr_prden_evts2 rw — 当TRIP10设置成周期性保护时，选择是否在CNT_PRD有效时清除对APTx_PWMA/APTx_PWMB的保护。 0：不使能； 1：使能。
  [20] rg_oc_clr_prden_evts1 rw — 当TRIP9设置成周期性保护时，选择是否在CNT_PRD有效时清除对APTx_PWMA/APTx_PWMB的保护。 0：不使能； 1：使能。
  [19] reserved ro — 保留。
  [18] rg_oc_clr_prden_evt3 rw — 当TRIP3设置成周期性保护时，选择是否在CNT_PRD有效时清除对APTx_PWMA/APTx_PWMB的保护。 0：不使能； 1：使能。
  [17] rg_oc_clr_prden_evt2 rw — 当TRIP2设置成周期性保护时，选择是否在CNT_PRD有效时清除对APTx_PWMA/APTx_PWMB的保护。 0：不使能； 1：使能。
  [16] rg_oc_clr_prden_evt1 rw — 当TRIP1设置成周期性保护时，选择是否在CNT_PRD有效时清除对APTx_PWMA/APTx_PWMB的保护。 0：不使能； 1：使能。
  [15:12] reserved ro — 保留。
  [11] rg_oc_clr_zroen_evtb2 rw — 当EMEVTB2设置成周期性保护时，选择是否在CNT_ZERO有效时清除对APTx_PWMA/APTx_PWMB的保护。 0：不使能； 1：使能。
  [10] rg_oc_clr_zroen_evtb1 rw — 当EMEVTB1设置成周期性保护时，选择是否在CNT_ZERO有效时清除对APTx_PWMA/APTx_PWMB的保护。 0：不使能； 1：使能。
  [9] rg_oc_clr_zroen_evta2 rw — 当EMEVTA2设置成周期性保护时，选择是否在CNT_ZERO有效时清除对APTx_PWMA/APTx_PWMB的保护。 0：不使能； 1：使能。
  [8] rg_oc_clr_zroen_evta1 rw — 当EMEVTA1设置成周期性保护时，选择是否在CNT_ZERO有效时清除对APTx_PWMA/APTx_PWMB的保护。 0：不使能； 1：使能。
  [7] reserved ro — 保留。
  [6] rg_oc_clr_zroen_evts3 rw — 当TRIP11设置成周期性保护时，选择是否在CNT_ZERO有效时清除对APTx_PWMA/APTx_PWMB的保护。 0：不使能； 1：使能。
  [5] rg_oc_clr_zroen_evts2 rw — 当TRIP10设置成周期性保护时，选择是否在CNT_ZERO有效时清除对APTx_PWMA/APTx_PWMB的保护。 0：不使能； 1：使能。
  [4] rg_oc_clr_zroen_evts1 rw — 当TRIP9设置成周期性保护时，选择是否在CNT_ZERO有效时清除对APTx_PWMA/APTx_PWMB的保护。 0：不使能； 1：使能。
  [3] reserved rw — 保留。
  [2] rg_oc_clr_zroen_evt3 rw — 当TRIP3设置成周期性保护时，选择是否在CNT_ZERO有效时清除对APTx_PWMA/APTx_PWMB的保护。 0：不使能； 1：使能。
  [1] rg_oc_clr_zroen_evt2 rw — 当TRIP2设置成周期性保护时，选择是否在CNT_ZERO有效时清除对APTx_PWMA/APTx_PWMB的保护。 0：不使能； 1：使能。
  [0] rg_oc_clr_zroen_evt1 rw — 当TRIP1设置成周期性保护时，选择是否在CNT_ZERO有效时清除对APTx_PWMA/APTx_PWMB的保护。 0：不使能； 1：使能。
0x330 OC_FRC_EVT — 强制产生故障信号寄存器。
  [31:12] reserved ro — 保留。
  [11] rg_oc_frc_evtb2 rw — 强制产生EMEVTB2故障信号。 0：无效； 1：有效。
  [10] rg_oc_frc_evtb1 rw — 强制产生EMEVTB1故障信号。 0：无效； 1：有效。
  [9] rg_oc_frc_evta2 rw — 强制产生EMEVTA2事件。 0：无效； 1：有效。
  [8] rg_oc_frc_evta1 rw — 强制产生EMEVTA1事件。 0：无效； 1：有效。
  [7] reserved ro — 保留。
  [6] rg_oc_frc_evts3 rw — 强制产生TRIP11故障信号。 0：无效； 1：有效。
  [5] rg_oc_frc_evts2 rw — 强制产生TRIP10故障信号。 0：无效； 1：有效。
  [4] rg_oc_frc_evts1 rw — 强制产生TRIP9故障信号。 0：无效； 1：有效。
  [3] reserved ro — 保留。
  [2] rg_oc_frc_evt3 rw — 强制产生TRIP3故障信号。 0：无效； 1：有效。
  [1] rg_oc_frc_evt2 rw — 强制产生TRIP2故障信号。 0：无效； 1：有效。
  [0] rg_oc_frc_evt1 rw — 强制产生TRIP1故障信号。 0：无效； 1：有效。
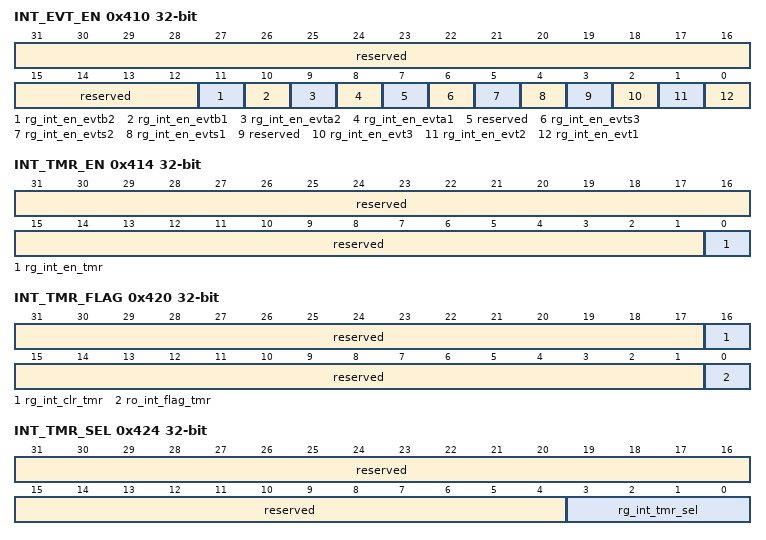
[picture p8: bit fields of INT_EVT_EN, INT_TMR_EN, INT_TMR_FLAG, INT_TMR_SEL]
0x410 INT_EVT_EN — 事件中断的中断使能寄存器。
  [31:12] reserved ro — 保留。
  [11] rg_int_en_evtb2 rw — EMEVTB2触发事件中断的使能位，选择故障信号EMEVTB2有效时，是否产生事件中断APTxEVTINT。 0：不使能； 1：使能。
  [10] rg_int_en_evtb1 rw — EMEVTB1触发事件中断的使能位，选择故障信号EMEVTB1有效时，是否产生事件中断APTxEVTINT。 0：不使能； 1：使能。
  [9] rg_int_en_evta2 rw — EMEVTA2触发事件中断的使能位，选择故障信号EMEVTA2有效时，是否产生事件中断APTxEVTINT。 0：不使能； 1：使能。
  [8] rg_int_en_evta1 rw — EMEVTA1触发事件中断的使能位，选择故障信号EMEVTA1有效时，是否产生事件中断APTxEVTINT。 0：不使能； 1：使能。
  [7] reserved ro — 保留。
  [6] rg_int_en_evts3 rw — TRIP11触发事件中断的使能位，选择故障信号TRIP11有效时，是否产生事件中断APTxEVTINT。 0：不使能； 1：使能。
  [5] rg_int_en_evts2 rw — TRIP10触发事件中断的使能位，选择故障信号TRIP10有效时，是否产生事件中断APTxEVTINT。 0：不使能； 1：使能。
  [4] rg_int_en_evts1 rw — TRIP9触发事件中断的使能位，选择故障信号TRIP9有效时，是否产生事件中断APTxEVTINT。 0：不使能； 1：使能。
  [3] reserved ro — 保留。
  [2] rg_int_en_evt3 rw — TRIP3触发事件中断的使能位，选择故障信号TRIP3有效时，是否产生事件中断APTxEVTINT。 0：不使能； 1：使能。
  [1] rg_int_en_evt2 rw — TRIP2触发事件中断的使能位，选择故障信号TRIP2有效时，是否产生事件中断APTxEVTINT。 0：不使能； 1：使能。
  [0] rg_int_en_evt1 rw — TRIP1触发事件中断的使能位，选择故障信号TRIP1有效时，是否产生事件中断APTxEVTINT。 0：不使能； 1：使能。
0x414 INT_TMR_EN — 定时中断使能寄存器。
  [31:1] reserved ro — 保留。
  [0] rg_int_en_tmr rw — 定时中断APTxTMRINT的使能位。 0：不使能； 1：使能。
0x420 INT_TMR_FLAG — 定时中断标志寄存器。
  [31:17] reserved ro — 保留。
  [16] rg_int_clr_tmr rw write-1-clears — 定时中断APTxTMRINT的中断清除位，写1清0。 0：写0无效； 1：写1有效。
  [15:1] reserved ro — 保留。
  [0] ro_int_flag_tmr ro — 定时中断APTxTMRINT的中断标志位。 0：APTxTMRINT无效； 1：APTxTMRINT有效。
0x424 INT_TMR_SEL — 定时中断的触发源选择寄存器。
  [31:4] reserved ro — 保留。
  [3:0] rg_int_tmr_sel rw — 定时中断APTxTMRINT的触发源选择。 0x1：CNT_ZERO有效； 0x2：CNT_PRD有效； 0x3：CNT_ZRO或CNT_PRD有效； 0x4：CNT_REFA有效且TCCNT计数方向递增； 0x5：CNT_REFA有效且TCCNT计数方向递减； 0x6：CNT_REFB有效且TCCNT计数方向递增； 0x7：CNT_REFB有效且TCCNT计数方向递减； 0x8：CNT_REFC有效且TCCNT计数方向递增； 0x9：CNT_REFC有效且TCCNT计数方向递减； 0xA：CNT_REFD有效且TCCNT计数方向递增； 0xB：CNT_REFD有效且TCCNT计数方向递减； 其它：保留。
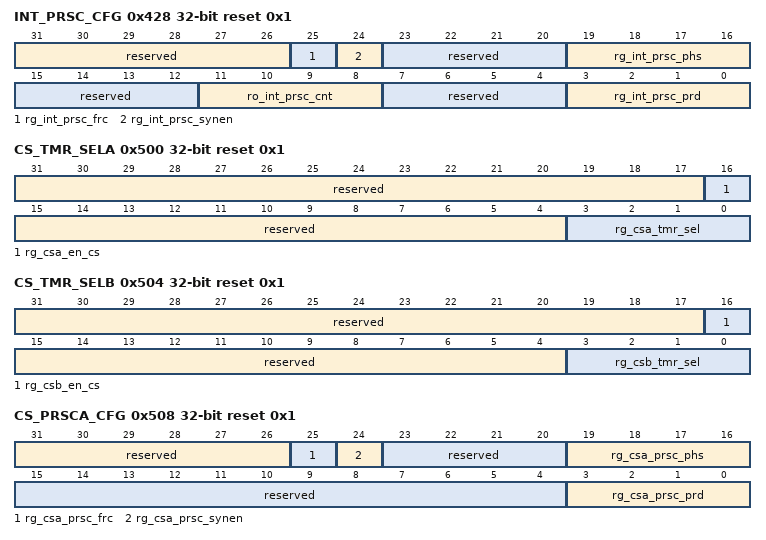
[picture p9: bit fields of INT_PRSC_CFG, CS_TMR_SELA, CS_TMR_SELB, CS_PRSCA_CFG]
0x428 INT_PRSC_CFG reset 0x1 — 定时中断缩减配置寄存器。
  [31:26] reserved ro — 保留。
  [25] rg_int_prsc_frc rw write-1-clears — 定时中断缩减计数器强制加1。 0：写0无效； 1：写1有效。
  [24] rg_int_prsc_synen rw — 定时中断缩减计数器的同步使能。 0：不使能； 1：使能。
  [23:20] reserved ro — 保留。
  [19:16] rg_int_prsc_phs rw — 定时中断缩减计数器的同步值。
  [15:12] reserved ro — 保留。
  [11:8] ro_int_prsc_cnt ro — 定时中断缩减计数器的计数值。
  [7:4] reserved ro — 保留。
  [3:0] rg_int_prsc_prd rw — 定时中断的缩减比例。 0x1：每发生1次有效的定时中断触发源，就产生定时中断； 0x2：每发生2次有效的定时中断触发源，就产生定时中断； 0x3：每发生3次有效的定时中断触发源，就产生定时中断； … 0xF：每发生15次有效的定时中断触发源，就产生定时中断。 其它：保留。
0x500 CS_TMR_SELA reset 0x1 — APTxSOCA 的触发源选择寄存器。
  [31:17] reserved ro — 保留。
  [16] rg_csa_en_cs rw — APTxSOCA 的使能位。 0：不使能； 1：使能。
  [15:4] reserved ro — 保留。
  [3:0] rg_csa_tmr_sel rw — APTxSOCA 的触发源选择。 0x0： EMEVTA1 有效； 0x1： CNT_ZERO 有效； 0x2： CNT_PRD 有效； 0x3： CNT_ZERO 或 CNT_PRD 有效； 0x4： CNT_REFA 有效且 TCCNT 计数方 向递增； 0x5： CNT_REFA 有效且 TCCNT 计数方 向递减； 0x6： CNT_REFB 有效且 TCCNT 计数方 向递增； 0x7： CNT_REFB 有效且 TCCNT 计数方 向递减； 0x8： CNT_REFC 有效且 TCCNT 计数方向递增； 0x9： CNT_REFC 有效且 TCCNT 计数方 向递减； 0xA： CNT_REFD 有效且 TCCNT 计数方 向递增； 0xB： CNT_REFD 有效且 TCCNT 计数方 向递减； 其它：保留。
0x504 CS_TMR_SELB reset 0x1 — APTxSOCB 的触发源选择寄存器。
  [31:17] reserved ro — 保留。
  [16] rg_csb_en_cs rw — APTxSOCB 的使能位。 0：不使能； 1：使能。
  [15:4] reserved ro — 保留。
  [3:0] rg_csb_tmr_sel rw — APTxSOCB 的触发源选择。 0x0： EMEVTB1 有效； 0x1： CNT_ZERO 有效； 0x2： CNT_PRD 有效； 0x3： CNT_ZERO 或 CNT_PRD 有效； 0x4： CNT_REFA 有效且 TCCNT 计数方 向递增； 0x5： CNT_REFA 有效且 TCCNT 计数方 向递减； 0x6： CNT_REFB 有效且 TCCNT 计数方 向递增； 0x7： CNT_REFB 有效且 TCCNT 计数方 向递减； 0x8： CNT_REFC 有效且 TCCNT 计数方 向递增； 0x9： CNT_REFC 有效且 TCCNT 计数方 向递减； 0xA： CNT_REFD 有效且 TCCNT 计数方 向递增； 0xB： CNT_REFD 有效且 TCCNT 计数方 向递减； 其它：保留。
0x508 CS_PRSCA_CFG reset 0x1 — APTxSOCA 缩减配置寄存器。
  [31:26] reserved ro — 保留。
  [25] rg_csa_prsc_frc rw write-1-clears — APTxSOCA 缩减计数器强制加 1。 0：写 0 无效； 1：写 1 有效。
  [24] rg_csa_prsc_synen rw — APTxSOCA 缩减计数器的同步使能。 0：不使能； 1：使能。
  [23:20] reserved ro — 保留。
  [19:16] rg_csa_prsc_phs rw — APTxSOCA 缩减计数器的同步值。
  [15:4] reserved ro — 保留。
  [3:0] rg_csa_prsc_prd rw — APTxSOCA 的缩减比例。 0x1：每发生 1 次有效的 APTxSOCA 的触发源，就产生 APTxSOCA； 0x2：每发生 2 次有效的 APTxSOCA 的 触发源，就产生 APTxSOCA； 0x3：每发生 3 次有效的 APTxSOCA 的 触发源，就产生 APTxSOCA； … 0xF：每发生 15 次有效的 APTxSOCA 的 触发源，就产生 APTxSOCA。 其它：保留。
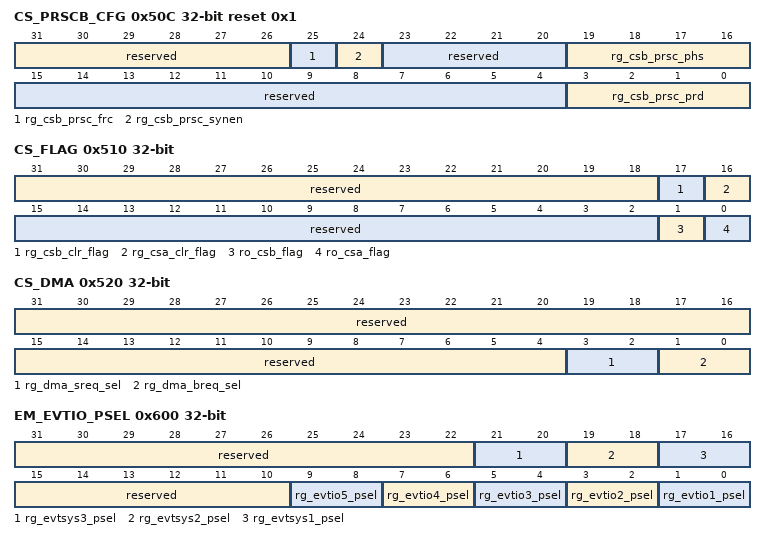
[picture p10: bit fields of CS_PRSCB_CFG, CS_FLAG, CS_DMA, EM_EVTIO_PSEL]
0x50C CS_PRSCB_CFG reset 0x1 — APTxSOCB 缩减配置寄存器。
  [31:26] reserved ro — 保留。
  [25] rg_csb_prsc_frc rw write-1-clears — APTxSOCB 缩减计数器强制加 1。 0：写 0 无效； 1：写 1 有效。
  [24] rg_csb_prsc_synen rw — APTxSOCB 缩减计数器的同步使能。 0：不使能； 1：使能。
  [23:20] reserved ro — 保留。
  [19:16] rg_csb_prsc_phs rw — APTxSOCB 缩减计数器的同步值。
  [15:4] reserved ro — 保留。
  [3:0] rg_csb_prsc_prd rw — APTxSOCB 的缩减比例。 0x1：每发生 1 次有效的 APTxSOCB 的 触发源，就产生 APTxSOCB； 0x2：每发生 2 次有效的 APTxSOCB 的 触发源，就产生 APTxSOCB； 0x3：每发生 3 次有效的 APTxSOCB 的 触发源，就产生 APTxSOCB； … 0xF：每发生 15 次有效的 APTxSOCB 的 触发源，就产生 APTxSOCB。 其它：保留。
0x510 CS_FLAG — APTxSOCA/APTxSOCB 标志寄存器。
  [31:18] reserved ro — 保留。
  [17] rg_csb_clr_flag rw write-1-clears — APTxSOCB 标志清除位，写 1 清 0。 0：写 0 无效； 1：写 1 有效。
  [16] rg_csa_clr_flag rw write-1-clears — APTxSOCA 标志清除位，写 1 清 0。 0：写 0 无效； 1：写 1 有效。
  [15:2] reserved ro — 保留。
  [1] ro_csb_flag ro — APTxSOCB 的标志位。 0：没有产生 APTxSOCB； 1：已经产生 APTxSOCB。
  [0] ro_csa_flag ro — APTxSOCA 的标志位。 0：没有产生 APTxSOCA； 1：已经产生 APTxSOCA。
0x520 CS_DMA — DMA 请求配置寄存器。
  [31:4] reserved ro — 保留。
  [3:2] rg_dma_sreq_sel rw — DMA Single 请求的触发源选择。 01： TRIGA 信号有效； 10： TRIGB 信号有效； 其它：禁止产生 DMA Single 请求。
  [1:0] rg_dma_breq_sel rw — DMA Burst 请求的源头选择。 01： TRIGA 信号有效； 10： TRIGB 信号有效； 其它：禁止产生 DMA Burst 请求。
0x600 EM_EVTIO_PSEL — 事件管理极性选择寄存器 1。
  [31:22] reserved ro — 保留。
  [21:20] rg_evtsys3_psel rw — TRIP11 的极性选择。 00： TRIP11 = sys_mem_fail； 01： TRIP11 = ~sys_mem_fail； 10： TRIP11 = 0； 11： TRIP11 = 1。
  [19:18] rg_evtsys2_psel rw — TRIP10 的极性选择。 00： TRIP10 = clock_fail； 01： TRIP10 = ~clock_fail； 10： TRIP10 = 0； 11： TRIP10 = 1。
  [17:16] rg_evtsys1_psel rw — TRIP9 的极性选择。 00： TRIP9 = debug_mode； 01： TRIP9 = ~debug_mode； 10： TRIP9 = 0； 11： TRIP9 = 1。
  [15:10] reserved ro — 保留。
  [9:8] rg_evtio5_psel rw — TRIP5 的极性选择。 00： TRIP5 = APT_EVTIO5； 01： TRIP5 = ~APT_EVTIO5； 10： TRIP5 = 0； 11： TRIP5 = 1。
  [7:6] rg_evtio4_psel rw — TRIP4 的极性选择。 00： TRIP4 = APT_EVTIO4； 01： TRIP4 = ~APT_EVTIO4； 10： TRIP4 = 0； 11： TRIP4 = 1。
  [5:4] rg_evtio3_psel rw — TRIP3 的极性选择。 00： TRIP3 = POE2； 01： TRIP3 = ~POE2； 10： TRIP3 = 0； 11： TRIP3 = 1。
  [3:2] rg_evtio2_psel rw — TRIP2 的极性选择。 00： TRIP2 = POE1； 01： TRIP2 = ~POE1； 10： TRIP2 = 0； 11： TRIP2 = 1。
  [1:0] rg_evtio1_psel rw — TRIP1 的极性选择。 00： TRIP1 = POE0； 01： TRIP1 = ~POE0； 10： TRIP1 = 0； 11： TRIP1 = 1
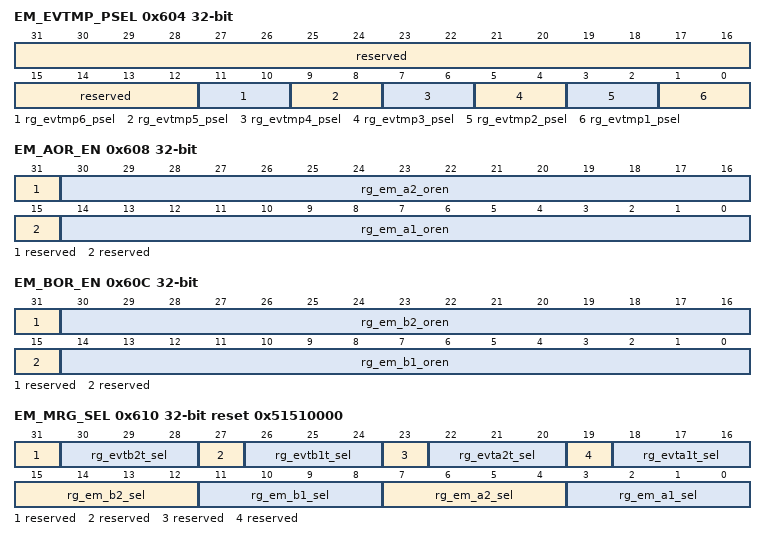
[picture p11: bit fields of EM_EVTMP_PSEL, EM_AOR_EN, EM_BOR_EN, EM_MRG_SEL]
0x604 EM_EVTMP_PSEL — 事件管理极性选择寄存器 2。
  [31:12] reserved ro — 保留。
  [11:10] rg_evtmp6_psel rw — TRIP8 的极性选择。 00： TRIP8 = APT_EVTMP6； 01： TRIP8 = ~APT_EVTMP6； 10： TRIP8 = 0； 11： TRIP8 = 1。
  [9:8] rg_evtmp5_psel rw — TRIP7 的极性选择。 00： TRIP7 = APT_EVTMP5； 01： TRIP7 = ~APT_EVTMP5； 10： TRIP7 = 0； 11： TRIP7 = 1。
  [7:6] rg_evtmp4_psel rw — TRIP6 的极性选择。 00： TRIP6 = APT_EVTMP4； 01： TRIP6 = ~APT_EVTMP4； 10： TRIP6 = 0； 11： TRIP6 = 1。
  [5:4] rg_evtmp3_psel rw — TRIP14 的极性选择。 00： TRIP14 = ACMP2_OUT； 01： TRIP14 = ~ACMP2_OUT； 10： TRIP14 = 0； 11： TRIP14 = 1。
  [3:2] rg_evtmp2_psel rw — TRIP13 的极性选择。 00： TRIP13 = ACMP1_OUT； 01： TRIP13 = ~ACMP1_OUT； 10： TRIP13 = 0； 11： TRIP13 = 1。
  [1:0] rg_evtmp1_psel rw — TRIP12 的极性选择。 00： TRIP12 = ACMP0_OUT； 01： TRIP12 = ~ACMP0_OUT； 10： TRIP12 = 0； 11： TRIP12 = 1。
0x608 EM_AOR_EN — 事件管理组合输入选择寄存器 A。
  [31] reserved ro — 保留。
  [30:16] rg_em_a2_oren rw — TRIP_OR_A2的触发源选择，每个比特对应一个信号。 bit[24]代表TRIP8的使能位； bit[23]代表TRIP7的使能位； bit[22]代表TRIP6的使能位； bit[21]代表TRIP14的使能位； bit[20]代表TRIP13的使能位； bit[19]代表TRIP12的使能位； bit[18]代表TRIP3的使能位； bit[17]代表TRIP2的使能位； bit[16]代表TRIP1的使能位； 其它比特无效，应配置为0。 当相应的比特为1时，代表对应的信号参与逻辑或； 当相应的比特为0时，代表对应的信号不参与逻辑或。
  [15] reserved ro — 保留。
  [14:0] rg_em_a1_oren rw — TRIP_OR_A1的触发源选择，每个比特对应一个信号。 bit[8]代表TRIP8的使能位； bit[7]代表TRIP7的使能位； bit[6]代表TRIP6的使能位； bit[5]代表TRIP14的使能位； bit[4]代表TRIP13的使能位； bit[3]代表TRIP12的使能位； bit[2]代表TRIP3的使能位； bit[1]代表TRIP2的使能位； bit[0]代表TRIP1的使能位； 其它比特无效，应配置为0。 当相应的比特为1时，代表对应的信号参与逻辑或； 当相应的比特为0时，代表对应的信号不参与逻辑或。
0x60C EM_BOR_EN — 事件管理组合输入选择寄存器 B。
  [31] reserved ro — 保留。
  [30:16] rg_em_b2_oren rw — TRIP_OR_B2 的触发源选择，每个比特对 应一个信号。 bit[24]代表TRIP8的使能位； bit[23]代表TRIP7的使能位； bit[22]代表TRIP6的使能位； bit[21]代表TRIP14的使能位； bit[20]代表TRIP13的使能位； bit[19]代表TRIP12的使能位； bit[18]代表TRIP3的使能位； bit[17]代表TRIP2的使能位； bit[16]代表TRIP1的使能位； 其它比特无效，应配置为 0。 当相应的比特为 1 时，代表对应的信号参 与逻辑或； 当相应的比特为 0 时，代表对应的信号不 参与逻辑或。
  [15] reserved ro — 保留。
  [14:0] rg_em_b1_oren rw — TRIP_OR_B1 的触发源选择，每个比特对 应一个信号。 bit[8]代表TRIP8的使能位； bit[7]代表TRIP7的使能位； bit[6]代表TRIP6的使能位； bit[5]代表TRIP14的使能位； bit[4]代表TRIP13的使能位； bit[3]代表TRIP12的使能位； bit[2]代表TRIP3的使能位； bit[1]代表TRIP2的使能位； bit[0]代表TRIP1的使能位； 其它比特无效，应配置为 0。 当相应的比特为 1 时，代表对应的信号参 与逻辑或； 当相应的比特为 0 时，代表对应的信号不 参与逻辑或。
0x610 EM_MRG_SEL reset 0x51510000 — 事件管理输入选择寄存器。
  [31] reserved ro — 保留。
  [30:28] rg_evtb2t_sel rw — EMEVTB2_TEMP 有效（高电平有效）的 条件选择。 001：EMEVTB1_SRC为高电平； 010：EMEVTB1_SRC为高电平，且EMEVTB2_SRC为低电平； 011：EMEVTB1_SRC为高电平，且EMEVTB2_SRC为高电平； 100：EMEVTB1_SRC为低电平，且EMEVTB2_SRC为高电平； 101：EMEVTB2_SRC为高电平； 其它： EMEVTB2_TEMP 输出低电平。
  [27] reserved ro — 保留。
  [26:24] rg_evtb1t_sel rw — EMEVTB1_TEMP 有效（高电平有效）的 条件选择。 001：EMEVTB1_SRC为高电平； 010：EMEVTB1_SRC为高电平，且EMEVTB2_SRC为低电平； 011：EMEVTB1_SRC为高电平，且EMEVTB2_SRC为高电平； 100：EMEVTB1_SRC为低电平，且EMEVTB2_SRC为高电平； 101：EMEVTB2_SRC为高电平； 其它： EMEVTB1_TEMP 输出低电平。
  [23] reserved ro — 保留。
  [22:20] rg_evta2t_sel rw — EMEVTA2_TEMP 有效（高电平有效）的 条件选择。 001：EMEVTA1_SRC为高电平； 010：EMEVTA1_SRC为高电平，且EMEVTA2_SRC为低电平； 011：EMEVTA1_SRC为高电平，且EMEVTA2_SRC为高电平； 100：EMEVTA1_SRC为低电平，且EMEVTA2_SRC为高电平； 101：EMEVTA2_SRC为高电平； 其它： EMEVTA2_TEMP 输出低电平。
  [19] reserved ro — 保留。
  [18:16] rg_evta1t_sel rw — EMEVTA1_TEMP 有效（高电平有效）的 条件选择。 001：EMEVTA1_SRC为高电平； 010：EMEVTA1_SRC为高电平，且EMEVTA2_SRC为低电平； 011：EMEVTA1_SRC为高电平，且EMEVTA2_SRC为高电平； 100：EMEVTA1_SRC为低电平，且EMEVTA2_SRC为高电平； 101：EMEVTA2_SRC为高电平；其它： EMEVTA1_TEMP 输出低电平。
  [15:12] rg_em_b2_sel rw — EMEVTB2_SRC 触发源选择。 0x0： TRIP1； 0x1： TRIP2； 0x2： TRIP3； 0x3： TRIP12； 0x4： TRIP13； 0x5： TRIP14； 0x6： TRIP6； 0x7： TRIP7； 0x8： TRIP8； 0xF： TRIP_OR_B2； 其它： EMEVTB2_SRC 输出低电平。
  [11:8] rg_em_b1_sel rw — EMEVTB1_SRC 触发源选择。 0x0： TRIP1； 0x1： TRIP2； 0x2： TRIP3； 0x3： TRIP12； 0x4： TRIP13； 0x5： TRIP14； 0x6： TRIP6； 0x7： TRIP7； 0x8： TRIP8； 0xF： TRIP_OR_B1； 其它： EMEVTB1_SRC 输出低电平。
  [7:4] rg_em_a2_sel rw — EMEVTA2_SRC 触发源选择。 0x0： TRIP1； 0x1： TRIP2； 0x2： TRIP3； 0x3： TRIP12； 0x4： TRIP13； 0x5： TRIP14； 0x6： TRIP6； 0x7： TRIP7； 0x8： TRIP8； 0xF： TRIP_OR_A2； 其它： EMEVTA2_SRC 输出低电平。
  [3:0] rg_em_a1_sel rw — EMEVTA1_SRC 触发源选择。 0x0： TRIP1； 0x1： TRIP2； 0x2： TRIP3； 0x3： TRIP12； 0x4： TRIP13； 0x5： TRIP14； 0x6： TRIP6； 0x7： TRIP7； 0x8： TRIP8； 0xF： TRIP_OR_A1； 其它： EMEVTA1_SRC 输出低电平。
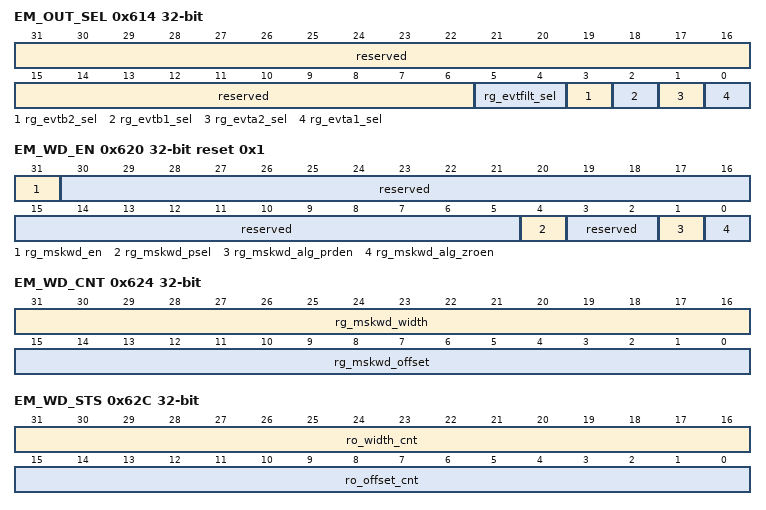
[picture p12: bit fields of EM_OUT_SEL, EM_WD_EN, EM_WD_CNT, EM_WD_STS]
0x614 EM_OUT_SEL — 事件管理输出选择寄存器。
  [31:6] reserved ro — 保留。
  [5:4] rg_evtfilt_sel rw — EMEVTFILT 的触发源选择。 00： EMEVTA1_TEMP； 01： EMEVTA2_TEMP； 10： EMEVTB1_TEMP； 11： EMEVTB2_TEMP。
  [3] rg_evtb2_sel rw — EMEVTB2 的触发源选择。 0： EMEVTB2_TEMP； 1： EMEVTFILT。
  [2] rg_evtb1_sel rw — EMEVTB1 的触发源选择。 0： EMEVTB1_TEMP； 1： EMEVTFILT。
  [1] rg_evta2_sel rw — EMEVTA2 的触发源选择。 0： EMEVTA2_TEMP； 1： EMEVTFILT。
  [0] rg_evta1_sel rw — EMEVTA1 的触发源选择。 0： EMEVTA1_TEMP； 1： EMEVTFILT。
0x620 EM_WD_EN reset 0x1 — 屏蔽窗口配置寄存器。
  [31] rg_mskwd_en rw — 屏蔽窗口 APTx_MSKWD 的使能位。 0：不使能， APTx_MSKWD 保持高电 平； 1：使能，按照配置产生屏蔽窗口 APTx_MSKWD。
  [30:5] reserved ro — 保留。
  [4] rg_mskwd_psel rw — 屏蔽窗口的极性选择。 0：屏蔽 APTx_MSKWD 内的事件； 1：屏蔽 APTx_MSKWD 外的事件。
  [3:2] reserved ro — 保留。
  [1] rg_mskwd_alg_prden rw — 当 CNT_PRD 有效时，选择是否重新开始 产生屏蔽窗口和 TCCNT 计数值捕获。 0：不使能； 1：使能。
  [0] rg_mskwd_alg_zroen rw — 当 CNT_ZERO 有效时，选择是否重新开 始产生屏蔽窗口和 TCCNT 计数值捕获。 0：不使能； 1：使能。
0x624 EM_WD_CNT rw — 屏蔽窗口计数寄存器。
  [31:16] rg_mskwd_width — 设置屏蔽窗口的宽度，建议不要超过一个 PWM 周期。单位等于 TCCNT 的一个计数 单位。
  [15:0] rg_mskwd_offset — 设置屏蔽窗口相对于对齐点的偏移量，建 议不要超过一个 PWM 周期。单位等于 TCCNT 的一个计数单位。
0x62C EM_WD_STS ro — 屏蔽窗口计数器状态寄存器。
  [31:16] ro_width_cnt — 屏蔽窗口的宽度计数值。
  [15:0] ro_offset_cnt — 屏蔽窗口的偏移计数值。
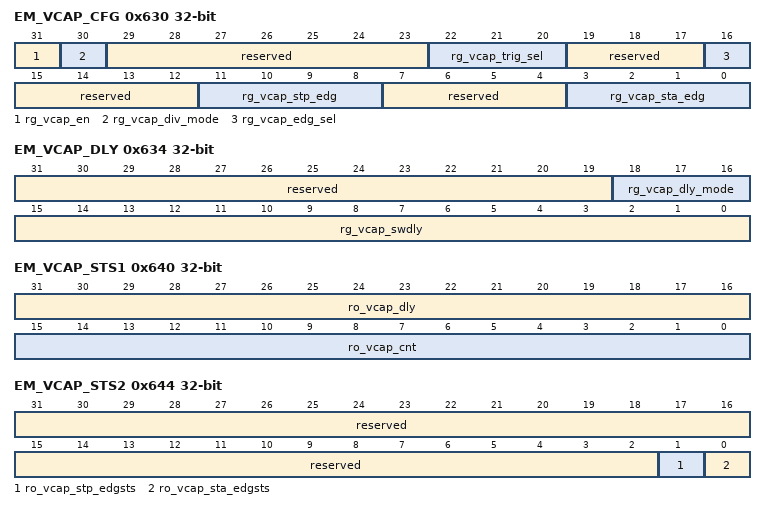
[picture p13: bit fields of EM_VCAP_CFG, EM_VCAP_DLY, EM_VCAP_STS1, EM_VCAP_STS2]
0x630 EM_VCAP_CFG — 谷底开关配置寄存器。
  [31] rg_vcap_en rw — 谷底开关功能使能位。 0：不使能谷底开关功能； 1：使能谷底开关功能。
  [30] rg_vcap_div_mode rw — 振荡周期测量逻辑的计数模式选择。 0：按照 APTCLK 时钟计数； 1：按照分频后的时钟计数。
  [29:23] reserved ro — 保留。
  [22:20] rg_vcap_trig_sel rw — 触发边沿滤波逻辑和振荡周期测量逻辑清 零和重启的条件选择。 000：禁止清零重启； 001： CNT_ZERO 有效； 010： CNT_PRD 有效； 011： CNT_ZERO 或 CNT_PRD 有效； 100： EMEVTA1_TEMP 有效； 101： EMEVTA2_TEMP 有效； 110： EMEVTB1_TEMP 有效； 111： EMEVTB2_TEMP 有效。
  [19:17] reserved ro — 保留。
  [16] rg_vcap_edg_sel rw — 振荡周期测量逻辑捕获 EMEVTMSK 的有 效沿。 0：上升沿； 1：下降沿。
  [15:12] reserved ro — 保留。
  [11:8] rg_vcap_stp_edg rw — 振荡周期测量逻辑停止测量的边沿。
  [7:4] reserved ro — 保留。
  [3:0] rg_vcap_sta_edg rw — 振荡周期测量逻辑开始测量的边沿。
0x634 EM_VCAP_DLY — 谷底开关失调补偿寄存器。
  [31:19] reserved ro — 保留。
  [18:16] rg_vcap_dly_mode rw — VCAPDLY 的选择。 001： VCAPHWDLY + rg_vcap_swdly； 010： VCAPHWDLY/2 + rg_vcap_swdly； 011： VCAPHWDLY/4 + rg_vcap_swdly； 100： VCAPHWDLY/8 + rg_vcap_swdly； 101： VCAPHWDLY/16 + rg_vcap_swdly； 110： VCAPHWDLY/32 + rg_vcap_swdly； 其它： rg_vcap_swdly。
  [15:0] rg_vcap_swdly rw — 软件添加的失调补偿值。
0x640 EM_VCAP_STS1 ro — 谷底开关捕获状态寄存器 1。
  [31:16] ro_vcap_dly — VCAPDLY 的值。
  [15:0] ro_vcap_cnt — VCAPHWDLY 的值。
0x644 EM_VCAP_STS2 ro — 谷底开关捕获状态寄存器 2。
  [31:2] reserved — 保留。
  [1] ro_vcap_stp_edgsts — 振荡周期测量逻辑成功捕获停止边沿的指 示。 0：还未捕获； 1：成功捕获。
  [0] ro_vcap_sta_edgsts — 振荡周期测量逻辑成功捕获开始边沿的指 示。 0：还未捕获； 1：成功捕获。
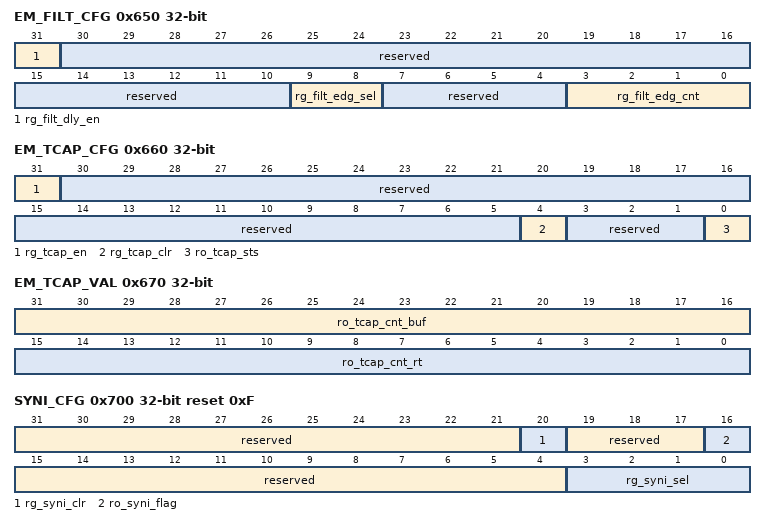
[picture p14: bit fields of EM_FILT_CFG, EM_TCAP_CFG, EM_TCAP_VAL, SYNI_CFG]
0x650 EM_FILT_CFG — 边沿滤波配置寄存器
  [31] rg_filt_dly_en rw — EMEVTFILT_TEMP 添加延时的使能位。 0：不使能， EMEVTFILT_TEMP 不添加任 何延时，直接生成 EMEVTFILT； 1：使能， EMEVTFILT_TEMP 经过延时 VCAPDLY 值后，生成 EMEVTFILT。
  [30:10] reserved ro — 保留。
  [9:8] rg_filt_edg_sel rw — EMEVTMSK 进行边沿滤波的有效边沿选 择。 0x：上升沿； 10：下降沿； 11：上升沿和下降沿。
  [7:4] reserved ro — 保留。
  [3:0] rg_filt_edg_cnt rw — 滤除的 EMEVTMSK 有效边沿个数的配 置，当检测到所配置个数的 EMEVTMSK 有效边沿后，输出 EMEVTFILT_TEMP 脉 冲。
0x660 EM_TCAP_CFG — TCCNT 计数值捕获配置寄存器。
  [31] rg_tcap_en rw — TCCNT 计数值捕获功能的使能位。 0：不使能，当 EMEVTFILT 有效时不捕 获 TCCNT 的计数值； 1：使能，当 EMEVTFILT 有效时捕获 TCCNT 的计数值。
  [30:5] reserved ro — 保留。
  [4] rg_tcap_clr rw write-1-clears — TCCNT 计数值捕获成功的标志清除位， 写 1 清 0。 0：写 0 无效； 1：写 1 清除 TCCNT 计数值捕获成功的 标志位 ro_tcap_sts。
  [3:1] reserved ro — 保留。
  [0] ro_tcap_sts ro — TCCNT 计数值捕获成功的标志位。 0：未捕获 TCCNT 计数值； 1：已捕获 TCCNT 计数值。
0x670 EM_TCAP_VAL ro — TCCNT 计数值捕获结果寄存器。
  [31:16] ro_tcap_cnt_buf — TCCNT 计数值捕获的缓存结果。每当启动 一次 TCCNT 计数值捕获时，将上一次捕 获的 TCCNT 计数值实时结果更新到缓存 结果。
  [15:0] ro_tcap_cnt_rt — TCCNT 计数值捕获的实时结果。每当启动 一次 TCCNT 计数值捕获时，实时结果清 零，当捕获成功时，将 TCCNT 计数器的 值保存，作为实时结果。
0x700 SYNI_CFG reset 0xF — 同步输入配置寄存器。
  [31:21] reserved ro — 保留。
  [20] rg_syni_clr rw write-1-clears — APTxSYNCI 的标志清除位，写 1 清 0。 0：写 0 无效； 1：写 1 清除 APTxSYNCI 的标志位 ro_syni_flag。
  [19:17] reserved ro — 保留。
  [16] ro_syni_flag ro — APTxSYNCI 的标志位。 0： APTxSYNCI 无效； 1： APTxSYNCI 有效。
  [15:4] reserved ro — 保留。
  [3:0] rg_syni_sel rw — APTxSYNCI 的触发源选择。 0x0： APT0SYNCO； 0x1： APT1SYNCO； 0x2： APT2SYNCO； 0x3： APT3SYNCO； 0x4： APT4SYNCO； 0x5： APT5SYNCO； 0x6： APT6SYNCO； 0x7： APT7SYNCO； 0x8： APT8SYNCO； 0x9： CAPM0SYNCO； 0xA： CAPM1SYNCO； 0xB： CAPM2SYNCO； 0xC： TRIP4； 0xD： TRIP5； 其它：禁止产生 APTxSYNCI。
0x704 SYNCNT_CFG — 计数器同步信号配置寄存器。
  [31:3] reserved ro — 保留。
  [2] rg_syncnt_synien rw — 当 APTxSYNCI 有效时，选择是否产生 APTCNTSYNC。 0：不使能； 1：使能。
  [1] rg_syncnt_b1en rw — 当 EMEVTB1 有效时，选择是否产生 APTCNTSYNC。 0：不使能； 1：使能。
  [0] rg_syncnt_a1en rw — 当 EMEVTA1 有效时，选择是否产生 APTCNTSYNC。
0x708 SYNO_CFG reset 0x1 — 同步输出配置寄存器。
  [31:11] reserved ro — 保留。
  [10] rg_latset_otsyn rw write-1-clears — 控制同步输出单次锁存器置位。 0：写 0 无效； 1：写 1 有效。
  [9] rg_latset_sel rw — 当选择单次同步输出模式，选择同步输出单次锁存器置位的条件。 0：向 SYNO_CFG[rg_latset_otsyn]写 1 时置位； 1：向 GLB_LOAD[rg_latset_otgld]写 1 时置位。
  [8] rg_mode_syno rw — 同步输出的模式选择。 0：单次同步输出； 1：不限次数同步输出。
  [7] rg_syno_refden rw — 当 CNT_REFD 有效时，选择是否产生APTxSYNCO。 0：不使能； 1：使能。
  [6] rg_syno_refcen rw — 当 CNT_REFC 有效时，选择是否产生APTxSYNCO。 0：不使能； 1：使能。
  [5] rg_syno_refben rw — 当 CNT_REFB 有效时，选择是否产生APTxSYNCO。 0：不使能； 1：使能。
  [4] reserved ro — 保留。
  [3] rg_syno_b1en rw — 当 EMEVTB1 有效时，选择是否产生APTxSYNCO。 0：不使能； 1：使能。
  [2] rg_syno_a1en rw — 当 EMEVTA1 有效时，选择是否产生APTxSYNCO。 0：不使能； 1：使能。
  [1] rg_syno_prden rw — 当 CNT_PRD 有效时，选择是否产生APTxSYNCO。 0：不使能； 1：使能。
  [0] rg_syno_zroen rw — 当 CNT_ZERO 有效时，选择是否产生APTxSYNCO。 0：不使能； 1：使能。
0x710 GLB_LOAD reset 0x1 — 全局加载配置寄存器。
  [31:17] reserved ro — 保留。
  [16] rg_latset_otgld rw write-1-clears — 控制全局加载单次锁存器置位。 0：写 0 无效； 1：写 1 有效。
  [15:13] reserved ro — 保留。
  [12] rg_mode_gld rw — 全局加载的模式选择。 0：单次加载； 1：不限次数加载。
  [11:8] rg_gld_prsc_prd rw — 全局加载信号缩减计数器的缩减比例。 0x1：每发生 1 次有效的全局加载触发信号，就产生 glb_ld； 0x2：每发生 2 次有效的全局加载触发信号，就产生 glb_ld； 0x3：每发生 3 次有效的全局加载触发信号，就产生 glb_ld； … 0xF：每发生 15 次有效的全局加载触发信号，就产生 glb_ld。 其它：保留。
  [7:3] reserved ro — 保留。
  [2] rg_gld_cntsynen rw — 使能 APTCNTSYNC 作为全局加载触发信号。 0：不使能； 1：使能。
  [1] rg_gld_prden rw — 使能 CNT_PRD 作为全局加载触发信号。 0：不使能； 1：使能。
  [0] rg_gld_zroen rw — 使能 CNT_ZERO 作为全局加载触发信号。 0：不使能； 1：使能。
0x720 LOAD_STS ro — 缓存状态寄存器。
  [31:15] reserved — 保留。
  [14] dg_cfg_ld_sts — 当使能了 DG_CFG 寄存器的缓存，指示DG_CFG 寄存器的缓存状态。 0：缓存寄存器空； 1：缓存寄存器满。
  [13] dg_fed_ld_sts — 当使能了 DG_FEG 寄存器的缓存，指示DG_FEG 寄存器的缓存状态。 0：缓存寄存器空； 1：缓存寄存器满。
  [12] dg_red_ld_sts — 当使能了 DG_REG 寄存器的缓存，指示DG_REG 寄存器的缓存状态。 0：缓存寄存器空； 1：缓存寄存器满。
  [11] reserved — 保留。
  [10] pg_out_frc_ld_sts — 当使能了 PG_ACT_FRC 寄存器的缓存，指示PG_ACT_FRC 寄存器的缓存状态。 0：缓存寄存器空； 1：缓存寄存器满。
  [9] pg_act_b_ld_sts — 当使能了 PG_ACT_B 寄存器的缓存，指示PG_ACT_B 寄存器的缓存状态。 0：缓存寄存器空； 1：缓存寄存器满。
  [8] pg_act_a_ld_sts — 当使能了 PG_ACT_A 寄存器的缓存，指示 PG_ACT_A 寄存器的缓存状态。 0：缓存寄存器空； 1：缓存寄存器满。
  [7:5] reserved — 保留。
  [4] tc_refd_ld_sts — 当使能了 TC_REFD 寄存器的缓存，指示TC_REFD 寄存器的缓存状态。 0：缓存寄存器空； 1：缓存寄存器满。
  [3] tc_refc_ld_sts — 当使能了 TC_REFC 寄存器的缓存，指示TC_REFC 寄存器的缓存状态。 0：缓存寄存器空； 1：缓存寄存器满。
  [2] tc_refb_ld_sts — 当使能了 TC_REFB 寄存器的缓存，指示TC_REFB 寄存器的缓存状态。 0：缓存寄存器空； 1：缓存寄存器满。
  [1] tc_refa_ld_sts — 当使能了 TC_REFA 寄存器的缓存，指示TC_REFA 寄存器的缓存状态。 0：缓存寄存器空； 1：缓存寄存器满。
  [0] tc_prd_ld_sts — 当使能了 TC_PRD 寄存器的缓存，指示TC_PRD 寄存器的缓存状态。 0：缓存寄存器空； 1：缓存寄存器满。
0x730 SYN_FRC — 软件强制寄存器。
  [31:29] reserved ro — 保留。
  [28] rg_synpg_frc rw write-1-clears — 强制产生一个 PG_ACT_A/PG_ACT_B 寄存器的独立加载的触发信号。 0：写 0 无效； 1：写 1 有效。
  [27:25] reserved ro — 保留。
  [24] rg_int_syn_frc rw write-1-clears — 强制定时中断缩减计数器更新成INT_PRSC_CFG[rg_int_prsc_phs]中的 值。 0：写 0 无效； 1：写 1 有效。
  [23:22] reserved ro — 保留。
  [21] rg_csb_syn_frc rw write-1-clears — 强制产生一次 APTxSOCB 的触发源。 0：写 0 无效； 1：写 1 有效。
  [20] rg_csa_syn_frc rw write-1-clears — 强制产生一次 APTxSOCA 的触发源。 0：写 0 无效； 1：写 1 有效。
  [19:17] reserved ro — 保留。
  [16] rg_vcap_frc rw write-1-clears — 强制边沿滤波逻辑和振荡周期测量逻辑清零和重启一次。 0：写 0 无效； 1：写 1 有效。
  [15:13] reserved ro — 保留。
  [12] rg_gld_frc rw write-1-clears — 强制产生一次全局加载信号的触发信号。 0：写 0 无效； 1：写 1 有效。
  [11:5] reserved ro — 保留。
  [4] rg_syno_frc rw write-1-clears — 强制产生一次 APTxSYNCO 的触发源。 0：写 0 无效； 1：写 1 有效。
  [3:1] reserved ro — 保留。
  [0] rg_syncnt_frc rw write-1-clears — 强制产生一个 APTCNTSYNC 信号。 0：写 0 无效； 1：写 1 有效。
